VERSION 5.8 ;
BUSBITCHARS "[]" ;
DIVIDERCHAR "/" ;
UNITS
    DATABASE MICRONS 1000 ;
END UNITS

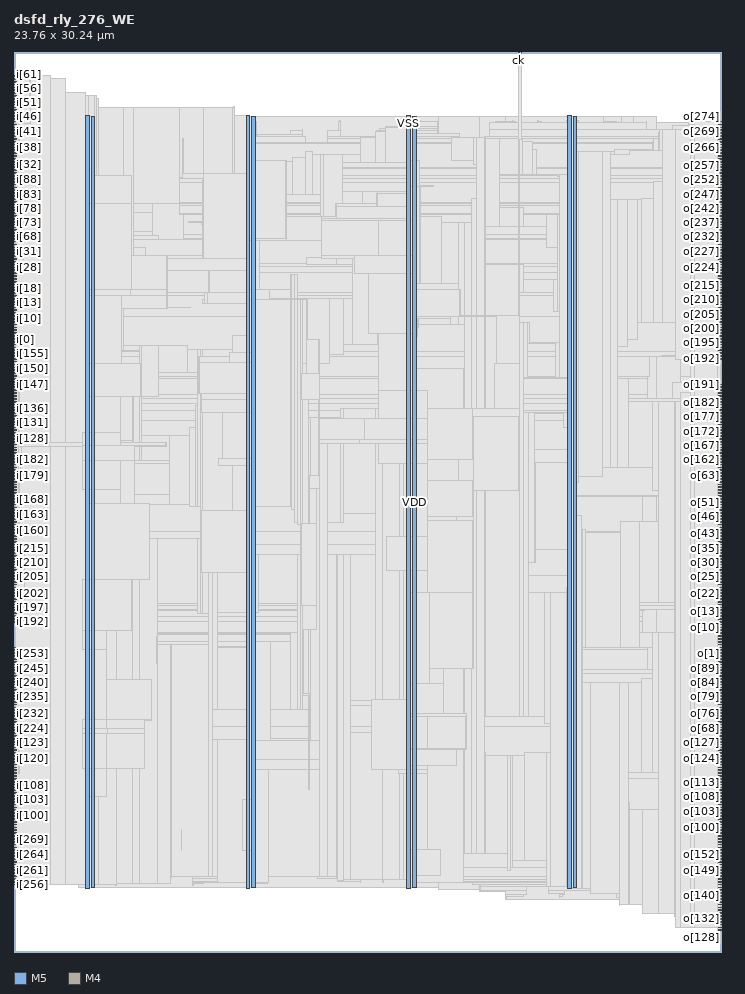
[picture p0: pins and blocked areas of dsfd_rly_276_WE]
MACRO dsfd_rly_276_WE
  FOREIGN dsfd_rly_276_WE 0 0 ;
  CLASS BLOCK ;
  SIZE 23.76 BY 30.24 ;
  PIN ck
    DIRECTION INPUT ;
    USE SIGNAL ;
    PORT
      LAYER M5 ;
        RECT  16.944 30.156 16.968 30.24 ;
    END
  END ck
  PIN i[0]
    DIRECTION INPUT ;
    USE SIGNAL ;
    PORT
      LAYER M4 ;
        RECT  0 20.304 0.084 20.328 ;
    END
  END i[0]
  PIN i[100]
    DIRECTION INPUT ;
    USE SIGNAL ;
    PORT
      LAYER M4 ;
        RECT  0 4.56 0.084 4.584 ;
    END
  END i[100]
  PIN i[101]
    DIRECTION INPUT ;
    USE SIGNAL ;
    PORT
      LAYER M4 ;
        RECT  0 4.656 0.084 4.68 ;
    END
  END i[101]
  PIN i[102]
    DIRECTION INPUT ;
    USE SIGNAL ;
    PORT
      LAYER M4 ;
        RECT  0 4.752 0.084 4.776 ;
    END
  END i[102]
  PIN i[103]
    DIRECTION INPUT ;
    USE SIGNAL ;
    PORT
      LAYER M4 ;
        RECT  0 4.848 0.084 4.872 ;
    END
  END i[103]
  PIN i[104]
    DIRECTION INPUT ;
    USE SIGNAL ;
    PORT
      LAYER M4 ;
        RECT  0 4.944 0.084 4.968 ;
    END
  END i[104]
  PIN i[105]
    DIRECTION INPUT ;
    USE SIGNAL ;
    PORT
      LAYER M4 ;
        RECT  0 5.04 0.084 5.064 ;
    END
  END i[105]
  PIN i[106]
    DIRECTION INPUT ;
    USE SIGNAL ;
    PORT
      LAYER M4 ;
        RECT  0 5.136 0.084 5.16 ;
    END
  END i[106]
  PIN i[107]
    DIRECTION INPUT ;
    USE SIGNAL ;
    PORT
      LAYER M4 ;
        RECT  0 5.232 0.084 5.256 ;
    END
  END i[107]
  PIN i[108]
    DIRECTION INPUT ;
    USE SIGNAL ;
    PORT
      LAYER M4 ;
        RECT  0 5.328 0.084 5.352 ;
    END
  END i[108]
  PIN i[109]
    DIRECTION INPUT ;
    USE SIGNAL ;
    PORT
      LAYER M4 ;
        RECT  0 5.424 0.084 5.448 ;
    END
  END i[109]
  PIN i[10]
    DIRECTION INPUT ;
    USE SIGNAL ;
    PORT
      LAYER M4 ;
        RECT  0 21.264 0.084 21.288 ;
    END
  END i[10]
  PIN i[110]
    DIRECTION INPUT ;
    USE SIGNAL ;
    PORT
      LAYER M4 ;
        RECT  0 5.52 0.084 5.544 ;
    END
  END i[110]
  PIN i[111]
    DIRECTION INPUT ;
    USE SIGNAL ;
    PORT
      LAYER M4 ;
        RECT  0 5.616 0.084 5.64 ;
    END
  END i[111]
  PIN i[112]
    DIRECTION INPUT ;
    USE SIGNAL ;
    PORT
      LAYER M4 ;
        RECT  0 5.712 0.084 5.736 ;
    END
  END i[112]
  PIN i[113]
    DIRECTION INPUT ;
    USE SIGNAL ;
    PORT
      LAYER M4 ;
        RECT  0 5.808 0.084 5.832 ;
    END
  END i[113]
  PIN i[114]
    DIRECTION INPUT ;
    USE SIGNAL ;
    PORT
      LAYER M4 ;
        RECT  0 5.904 0.084 5.928 ;
    END
  END i[114]
  PIN i[115]
    DIRECTION INPUT ;
    USE SIGNAL ;
    PORT
      LAYER M4 ;
        RECT  0 6 0.084 6.024 ;
    END
  END i[115]
  PIN i[116]
    DIRECTION INPUT ;
    USE SIGNAL ;
    PORT
      LAYER M4 ;
        RECT  0 6.096 0.084 6.12 ;
    END
  END i[116]
  PIN i[117]
    DIRECTION INPUT ;
    USE SIGNAL ;
    PORT
      LAYER M4 ;
        RECT  0 6.192 0.084 6.216 ;
    END
  END i[117]
  PIN i[118]
    DIRECTION INPUT ;
    USE SIGNAL ;
    PORT
      LAYER M4 ;
        RECT  0 6.288 0.084 6.312 ;
    END
  END i[118]
  PIN i[119]
    DIRECTION INPUT ;
    USE SIGNAL ;
    PORT
      LAYER M4 ;
        RECT  0 6.384 0.084 6.408 ;
    END
  END i[119]
  PIN i[11]
    DIRECTION INPUT ;
    USE SIGNAL ;
    PORT
      LAYER M4 ;
        RECT  0 21.36 0.084 21.384 ;
    END
  END i[11]
  PIN i[120]
    DIRECTION INPUT ;
    USE SIGNAL ;
    PORT
      LAYER M4 ;
        RECT  0 6.48 0.084 6.504 ;
    END
  END i[120]
  PIN i[121]
    DIRECTION INPUT ;
    USE SIGNAL ;
    PORT
      LAYER M4 ;
        RECT  0 6.576 0.084 6.6 ;
    END
  END i[121]
  PIN i[122]
    DIRECTION INPUT ;
    USE SIGNAL ;
    PORT
      LAYER M4 ;
        RECT  0 6.672 0.084 6.696 ;
    END
  END i[122]
  PIN i[123]
    DIRECTION INPUT ;
    USE SIGNAL ;
    PORT
      LAYER M4 ;
        RECT  0 6.768 0.084 6.792 ;
    END
  END i[123]
  PIN i[124]
    DIRECTION INPUT ;
    USE SIGNAL ;
    PORT
      LAYER M4 ;
        RECT  0 6.864 0.084 6.888 ;
    END
  END i[124]
  PIN i[125]
    DIRECTION INPUT ;
    USE SIGNAL ;
    PORT
      LAYER M4 ;
        RECT  0 6.96 0.084 6.984 ;
    END
  END i[125]
  PIN i[126]
    DIRECTION INPUT ;
    USE SIGNAL ;
    PORT
      LAYER M4 ;
        RECT  0 7.056 0.084 7.08 ;
    END
  END i[126]
  PIN i[127]
    DIRECTION INPUT ;
    USE SIGNAL ;
    PORT
      LAYER M4 ;
        RECT  0 7.152 0.084 7.176 ;
    END
  END i[127]
  PIN i[128]
    DIRECTION INPUT ;
    USE SIGNAL ;
    PORT
      LAYER M4 ;
        RECT  0 17.232 0.084 17.256 ;
    END
  END i[128]
  PIN i[129]
    DIRECTION INPUT ;
    USE SIGNAL ;
    PORT
      LAYER M4 ;
        RECT  0 17.328 0.084 17.352 ;
    END
  END i[129]
  PIN i[12]
    DIRECTION INPUT ;
    USE SIGNAL ;
    PORT
      LAYER M4 ;
        RECT  0 21.456 0.084 21.48 ;
    END
  END i[12]
  PIN i[130]
    DIRECTION INPUT ;
    USE SIGNAL ;
    PORT
      LAYER M4 ;
        RECT  0 17.424 0.084 17.448 ;
    END
  END i[130]
  PIN i[131]
    DIRECTION INPUT ;
    USE SIGNAL ;
    PORT
      LAYER M4 ;
        RECT  0 17.52 0.084 17.544 ;
    END
  END i[131]
  PIN i[132]
    DIRECTION INPUT ;
    USE SIGNAL ;
    PORT
      LAYER M4 ;
        RECT  0 17.616 0.084 17.64 ;
    END
  END i[132]
  PIN i[133]
    DIRECTION INPUT ;
    USE SIGNAL ;
    PORT
      LAYER M4 ;
        RECT  0 17.712 0.084 17.736 ;
    END
  END i[133]
  PIN i[134]
    DIRECTION INPUT ;
    USE SIGNAL ;
    PORT
      LAYER M4 ;
        RECT  0 17.808 0.084 17.832 ;
    END
  END i[134]
  PIN i[135]
    DIRECTION INPUT ;
    USE SIGNAL ;
    PORT
      LAYER M4 ;
        RECT  0 17.904 0.084 17.928 ;
    END
  END i[135]
  PIN i[136]
    DIRECTION INPUT ;
    USE SIGNAL ;
    PORT
      LAYER M4 ;
        RECT  0 18 0.084 18.024 ;
    END
  END i[136]
  PIN i[137]
    DIRECTION INPUT ;
    USE SIGNAL ;
    PORT
      LAYER M4 ;
        RECT  0 18.096 0.084 18.12 ;
    END
  END i[137]
  PIN i[138]
    DIRECTION INPUT ;
    USE SIGNAL ;
    PORT
      LAYER M4 ;
        RECT  0 18.192 0.084 18.216 ;
    END
  END i[138]
  PIN i[139]
    DIRECTION INPUT ;
    USE SIGNAL ;
    PORT
      LAYER M4 ;
        RECT  0 18.288 0.084 18.312 ;
    END
  END i[139]
  PIN i[13]
    DIRECTION INPUT ;
    USE SIGNAL ;
    PORT
      LAYER M4 ;
        RECT  0 21.552 0.084 21.576 ;
    END
  END i[13]
  PIN i[140]
    DIRECTION INPUT ;
    USE SIGNAL ;
    PORT
      LAYER M4 ;
        RECT  0 18.384 0.084 18.408 ;
    END
  END i[140]
  PIN i[141]
    DIRECTION INPUT ;
    USE SIGNAL ;
    PORT
      LAYER M4 ;
        RECT  0 18.48 0.084 18.504 ;
    END
  END i[141]
  PIN i[142]
    DIRECTION INPUT ;
    USE SIGNAL ;
    PORT
      LAYER M4 ;
        RECT  0 18.576 0.084 18.6 ;
    END
  END i[142]
  PIN i[143]
    DIRECTION INPUT ;
    USE SIGNAL ;
    PORT
      LAYER M4 ;
        RECT  0 18.672 0.084 18.696 ;
    END
  END i[143]
  PIN i[144]
    DIRECTION INPUT ;
    USE SIGNAL ;
    PORT
      LAYER M4 ;
        RECT  0 18.768 0.084 18.792 ;
    END
  END i[144]
  PIN i[145]
    DIRECTION INPUT ;
    USE SIGNAL ;
    PORT
      LAYER M4 ;
        RECT  0 18.864 0.084 18.888 ;
    END
  END i[145]
  PIN i[146]
    DIRECTION INPUT ;
    USE SIGNAL ;
    PORT
      LAYER M4 ;
        RECT  0 18.96 0.084 18.984 ;
    END
  END i[146]
  PIN i[147]
    DIRECTION INPUT ;
    USE SIGNAL ;
    PORT
      LAYER M4 ;
        RECT  0 19.056 0.084 19.08 ;
    END
  END i[147]
  PIN i[148]
    DIRECTION INPUT ;
    USE SIGNAL ;
    PORT
      LAYER M4 ;
        RECT  0 19.152 0.084 19.176 ;
    END
  END i[148]
  PIN i[149]
    DIRECTION INPUT ;
    USE SIGNAL ;
    PORT
      LAYER M4 ;
        RECT  0 19.248 0.084 19.272 ;
    END
  END i[149]
  PIN i[14]
    DIRECTION INPUT ;
    USE SIGNAL ;
    PORT
      LAYER M4 ;
        RECT  0 21.648 0.084 21.672 ;
    END
  END i[14]
  PIN i[150]
    DIRECTION INPUT ;
    USE SIGNAL ;
    PORT
      LAYER M4 ;
        RECT  0 19.344 0.084 19.368 ;
    END
  END i[150]
  PIN i[151]
    DIRECTION INPUT ;
    USE SIGNAL ;
    PORT
      LAYER M4 ;
        RECT  0 19.44 0.084 19.464 ;
    END
  END i[151]
  PIN i[152]
    DIRECTION INPUT ;
    USE SIGNAL ;
    PORT
      LAYER M4 ;
        RECT  0 19.536 0.084 19.56 ;
    END
  END i[152]
  PIN i[153]
    DIRECTION INPUT ;
    USE SIGNAL ;
    PORT
      LAYER M4 ;
        RECT  0 19.632 0.084 19.656 ;
    END
  END i[153]
  PIN i[154]
    DIRECTION INPUT ;
    USE SIGNAL ;
    PORT
      LAYER M4 ;
        RECT  0 19.728 0.084 19.752 ;
    END
  END i[154]
  PIN i[155]
    DIRECTION INPUT ;
    USE SIGNAL ;
    PORT
      LAYER M4 ;
        RECT  0 19.824 0.084 19.848 ;
    END
  END i[155]
  PIN i[156]
    DIRECTION INPUT ;
    USE SIGNAL ;
    PORT
      LAYER M4 ;
        RECT  0 19.92 0.084 19.944 ;
    END
  END i[156]
  PIN i[157]
    DIRECTION INPUT ;
    USE SIGNAL ;
    PORT
      LAYER M4 ;
        RECT  0 20.016 0.084 20.04 ;
    END
  END i[157]
  PIN i[158]
    DIRECTION INPUT ;
    USE SIGNAL ;
    PORT
      LAYER M4 ;
        RECT  0 20.112 0.084 20.136 ;
    END
  END i[158]
  PIN i[159]
    DIRECTION INPUT ;
    USE SIGNAL ;
    PORT
      LAYER M4 ;
        RECT  0 20.208 0.084 20.232 ;
    END
  END i[159]
  PIN i[15]
    DIRECTION INPUT ;
    USE SIGNAL ;
    PORT
      LAYER M4 ;
        RECT  0 21.744 0.084 21.768 ;
    END
  END i[15]
  PIN i[160]
    DIRECTION INPUT ;
    USE SIGNAL ;
    PORT
      LAYER M4 ;
        RECT  0 14.16 0.084 14.184 ;
    END
  END i[160]
  PIN i[161]
    DIRECTION INPUT ;
    USE SIGNAL ;
    PORT
      LAYER M4 ;
        RECT  0 14.256 0.084 14.28 ;
    END
  END i[161]
  PIN i[162]
    DIRECTION INPUT ;
    USE SIGNAL ;
    PORT
      LAYER M4 ;
        RECT  0 14.352 0.084 14.376 ;
    END
  END i[162]
  PIN i[163]
    DIRECTION INPUT ;
    USE SIGNAL ;
    PORT
      LAYER M4 ;
        RECT  0 14.448 0.084 14.472 ;
    END
  END i[163]
  PIN i[164]
    DIRECTION INPUT ;
    USE SIGNAL ;
    PORT
      LAYER M4 ;
        RECT  0 14.544 0.084 14.568 ;
    END
  END i[164]
  PIN i[165]
    DIRECTION INPUT ;
    USE SIGNAL ;
    PORT
      LAYER M4 ;
        RECT  0 14.64 0.084 14.664 ;
    END
  END i[165]
  PIN i[166]
    DIRECTION INPUT ;
    USE SIGNAL ;
    PORT
      LAYER M4 ;
        RECT  0 14.736 0.084 14.76 ;
    END
  END i[166]
  PIN i[167]
    DIRECTION INPUT ;
    USE SIGNAL ;
    PORT
      LAYER M4 ;
        RECT  0 14.832 0.084 14.856 ;
    END
  END i[167]
  PIN i[168]
    DIRECTION INPUT ;
    USE SIGNAL ;
    PORT
      LAYER M4 ;
        RECT  0 14.928 0.084 14.952 ;
    END
  END i[168]
  PIN i[169]
    DIRECTION INPUT ;
    USE SIGNAL ;
    PORT
      LAYER M4 ;
        RECT  0 15.024 0.084 15.048 ;
    END
  END i[169]
  PIN i[16]
    DIRECTION INPUT ;
    USE SIGNAL ;
    PORT
      LAYER M4 ;
        RECT  0 21.84 0.084 21.864 ;
    END
  END i[16]
  PIN i[170]
    DIRECTION INPUT ;
    USE SIGNAL ;
    PORT
      LAYER M4 ;
        RECT  0 15.12 0.084 15.144 ;
    END
  END i[170]
  PIN i[171]
    DIRECTION INPUT ;
    USE SIGNAL ;
    PORT
      LAYER M4 ;
        RECT  0 15.216 0.084 15.24 ;
    END
  END i[171]
  PIN i[172]
    DIRECTION INPUT ;
    USE SIGNAL ;
    PORT
      LAYER M4 ;
        RECT  0 15.312 0.084 15.336 ;
    END
  END i[172]
  PIN i[173]
    DIRECTION INPUT ;
    USE SIGNAL ;
    PORT
      LAYER M4 ;
        RECT  0 15.408 0.084 15.432 ;
    END
  END i[173]
  PIN i[174]
    DIRECTION INPUT ;
    USE SIGNAL ;
    PORT
      LAYER M4 ;
        RECT  0 15.504 0.084 15.528 ;
    END
  END i[174]
  PIN i[175]
    DIRECTION INPUT ;
    USE SIGNAL ;
    PORT
      LAYER M4 ;
        RECT  0 15.6 0.084 15.624 ;
    END
  END i[175]
  PIN i[176]
    DIRECTION INPUT ;
    USE SIGNAL ;
    PORT
      LAYER M4 ;
        RECT  0 15.696 0.084 15.72 ;
    END
  END i[176]
  PIN i[177]
    DIRECTION INPUT ;
    USE SIGNAL ;
    PORT
      LAYER M4 ;
        RECT  0 15.792 0.084 15.816 ;
    END
  END i[177]
  PIN i[178]
    DIRECTION INPUT ;
    USE SIGNAL ;
    PORT
      LAYER M4 ;
        RECT  0 15.888 0.084 15.912 ;
    END
  END i[178]
  PIN i[179]
    DIRECTION INPUT ;
    USE SIGNAL ;
    PORT
      LAYER M4 ;
        RECT  0 15.984 0.084 16.008 ;
    END
  END i[179]
  PIN i[17]
    DIRECTION INPUT ;
    USE SIGNAL ;
    PORT
      LAYER M4 ;
        RECT  0 21.936 0.084 21.96 ;
    END
  END i[17]
  PIN i[180]
    DIRECTION INPUT ;
    USE SIGNAL ;
    PORT
      LAYER M4 ;
        RECT  0 16.08 0.084 16.104 ;
    END
  END i[180]
  PIN i[181]
    DIRECTION INPUT ;
    USE SIGNAL ;
    PORT
      LAYER M4 ;
        RECT  0 16.176 0.084 16.2 ;
    END
  END i[181]
  PIN i[182]
    DIRECTION INPUT ;
    USE SIGNAL ;
    PORT
      LAYER M4 ;
        RECT  0 16.272 0.084 16.296 ;
    END
  END i[182]
  PIN i[183]
    DIRECTION INPUT ;
    USE SIGNAL ;
    PORT
      LAYER M4 ;
        RECT  0 16.368 0.084 16.392 ;
    END
  END i[183]
  PIN i[184]
    DIRECTION INPUT ;
    USE SIGNAL ;
    PORT
      LAYER M4 ;
        RECT  0 16.464 0.084 16.488 ;
    END
  END i[184]
  PIN i[185]
    DIRECTION INPUT ;
    USE SIGNAL ;
    PORT
      LAYER M4 ;
        RECT  0 16.56 0.084 16.584 ;
    END
  END i[185]
  PIN i[186]
    DIRECTION INPUT ;
    USE SIGNAL ;
    PORT
      LAYER M4 ;
        RECT  0 16.656 0.084 16.68 ;
    END
  END i[186]
  PIN i[187]
    DIRECTION INPUT ;
    USE SIGNAL ;
    PORT
      LAYER M4 ;
        RECT  0 16.752 0.084 16.776 ;
    END
  END i[187]
  PIN i[188]
    DIRECTION INPUT ;
    USE SIGNAL ;
    PORT
      LAYER M4 ;
        RECT  0 16.848 0.084 16.872 ;
    END
  END i[188]
  PIN i[189]
    DIRECTION INPUT ;
    USE SIGNAL ;
    PORT
      LAYER M4 ;
        RECT  0 16.944 0.084 16.968 ;
    END
  END i[189]
  PIN i[18]
    DIRECTION INPUT ;
    USE SIGNAL ;
    PORT
      LAYER M4 ;
        RECT  0 22.032 0.084 22.056 ;
    END
  END i[18]
  PIN i[190]
    DIRECTION INPUT ;
    USE SIGNAL ;
    PORT
      LAYER M4 ;
        RECT  0 17.04 0.084 17.064 ;
    END
  END i[190]
  PIN i[191]
    DIRECTION INPUT ;
    USE SIGNAL ;
    PORT
      LAYER M4 ;
        RECT  0 17.136 0.084 17.16 ;
    END
  END i[191]
  PIN i[192]
    DIRECTION INPUT ;
    USE SIGNAL ;
    PORT
      LAYER M4 ;
        RECT  0 11.088 0.084 11.112 ;
    END
  END i[192]
  PIN i[193]
    DIRECTION INPUT ;
    USE SIGNAL ;
    PORT
      LAYER M4 ;
        RECT  0 11.184 0.084 11.208 ;
    END
  END i[193]
  PIN i[194]
    DIRECTION INPUT ;
    USE SIGNAL ;
    PORT
      LAYER M4 ;
        RECT  0 11.28 0.084 11.304 ;
    END
  END i[194]
  PIN i[195]
    DIRECTION INPUT ;
    USE SIGNAL ;
    PORT
      LAYER M4 ;
        RECT  0 11.376 0.084 11.4 ;
    END
  END i[195]
  PIN i[196]
    DIRECTION INPUT ;
    USE SIGNAL ;
    PORT
      LAYER M4 ;
        RECT  0 11.472 0.084 11.496 ;
    END
  END i[196]
  PIN i[197]
    DIRECTION INPUT ;
    USE SIGNAL ;
    PORT
      LAYER M4 ;
        RECT  0 11.568 0.084 11.592 ;
    END
  END i[197]
  PIN i[198]
    DIRECTION INPUT ;
    USE SIGNAL ;
    PORT
      LAYER M4 ;
        RECT  0 11.664 0.084 11.688 ;
    END
  END i[198]
  PIN i[199]
    DIRECTION INPUT ;
    USE SIGNAL ;
    PORT
      LAYER M4 ;
        RECT  0 11.76 0.084 11.784 ;
    END
  END i[199]
  PIN i[19]
    DIRECTION INPUT ;
    USE SIGNAL ;
    PORT
      LAYER M4 ;
        RECT  0 22.128 0.084 22.152 ;
    END
  END i[19]
  PIN i[1]
    DIRECTION INPUT ;
    USE SIGNAL ;
    PORT
      LAYER M4 ;
        RECT  0 20.4 0.084 20.424 ;
    END
  END i[1]
  PIN i[200]
    DIRECTION INPUT ;
    USE SIGNAL ;
    PORT
      LAYER M4 ;
        RECT  0 11.856 0.084 11.88 ;
    END
  END i[200]
  PIN i[201]
    DIRECTION INPUT ;
    USE SIGNAL ;
    PORT
      LAYER M4 ;
        RECT  0 11.952 0.084 11.976 ;
    END
  END i[201]
  PIN i[202]
    DIRECTION INPUT ;
    USE SIGNAL ;
    PORT
      LAYER M4 ;
        RECT  0 12.048 0.084 12.072 ;
    END
  END i[202]
  PIN i[203]
    DIRECTION INPUT ;
    USE SIGNAL ;
    PORT
      LAYER M4 ;
        RECT  0 12.144 0.084 12.168 ;
    END
  END i[203]
  PIN i[204]
    DIRECTION INPUT ;
    USE SIGNAL ;
    PORT
      LAYER M4 ;
        RECT  0 12.24 0.084 12.264 ;
    END
  END i[204]
  PIN i[205]
    DIRECTION INPUT ;
    USE SIGNAL ;
    PORT
      LAYER M4 ;
        RECT  0 12.336 0.084 12.36 ;
    END
  END i[205]
  PIN i[206]
    DIRECTION INPUT ;
    USE SIGNAL ;
    PORT
      LAYER M4 ;
        RECT  0 12.432 0.084 12.456 ;
    END
  END i[206]
  PIN i[207]
    DIRECTION INPUT ;
    USE SIGNAL ;
    PORT
      LAYER M4 ;
        RECT  0 12.528 0.084 12.552 ;
    END
  END i[207]
  PIN i[208]
    DIRECTION INPUT ;
    USE SIGNAL ;
    PORT
      LAYER M4 ;
        RECT  0 12.624 0.084 12.648 ;
    END
  END i[208]
  PIN i[209]
    DIRECTION INPUT ;
    USE SIGNAL ;
    PORT
      LAYER M4 ;
        RECT  0 12.72 0.084 12.744 ;
    END
  END i[209]
  PIN i[20]
    DIRECTION INPUT ;
    USE SIGNAL ;
    PORT
      LAYER M4 ;
        RECT  0 22.224 0.084 22.248 ;
    END
  END i[20]
  PIN i[210]
    DIRECTION INPUT ;
    USE SIGNAL ;
    PORT
      LAYER M4 ;
        RECT  0 12.816 0.084 12.84 ;
    END
  END i[210]
  PIN i[211]
    DIRECTION INPUT ;
    USE SIGNAL ;
    PORT
      LAYER M4 ;
        RECT  0 12.912 0.084 12.936 ;
    END
  END i[211]
  PIN i[212]
    DIRECTION INPUT ;
    USE SIGNAL ;
    PORT
      LAYER M4 ;
        RECT  0 13.008 0.084 13.032 ;
    END
  END i[212]
  PIN i[213]
    DIRECTION INPUT ;
    USE SIGNAL ;
    PORT
      LAYER M4 ;
        RECT  0 13.104 0.084 13.128 ;
    END
  END i[213]
  PIN i[214]
    DIRECTION INPUT ;
    USE SIGNAL ;
    PORT
      LAYER M4 ;
        RECT  0 13.2 0.084 13.224 ;
    END
  END i[214]
  PIN i[215]
    DIRECTION INPUT ;
    USE SIGNAL ;
    PORT
      LAYER M4 ;
        RECT  0 13.296 0.084 13.32 ;
    END
  END i[215]
  PIN i[216]
    DIRECTION INPUT ;
    USE SIGNAL ;
    PORT
      LAYER M4 ;
        RECT  0 13.392 0.084 13.416 ;
    END
  END i[216]
  PIN i[217]
    DIRECTION INPUT ;
    USE SIGNAL ;
    PORT
      LAYER M4 ;
        RECT  0 13.488 0.084 13.512 ;
    END
  END i[217]
  PIN i[218]
    DIRECTION INPUT ;
    USE SIGNAL ;
    PORT
      LAYER M4 ;
        RECT  0 13.584 0.084 13.608 ;
    END
  END i[218]
  PIN i[219]
    DIRECTION INPUT ;
    USE SIGNAL ;
    PORT
      LAYER M4 ;
        RECT  0 13.68 0.084 13.704 ;
    END
  END i[219]
  PIN i[21]
    DIRECTION INPUT ;
    USE SIGNAL ;
    PORT
      LAYER M4 ;
        RECT  0 22.32 0.084 22.344 ;
    END
  END i[21]
  PIN i[220]
    DIRECTION INPUT ;
    USE SIGNAL ;
    PORT
      LAYER M4 ;
        RECT  0 13.776 0.084 13.8 ;
    END
  END i[220]
  PIN i[221]
    DIRECTION INPUT ;
    USE SIGNAL ;
    PORT
      LAYER M4 ;
        RECT  0 13.872 0.084 13.896 ;
    END
  END i[221]
  PIN i[222]
    DIRECTION INPUT ;
    USE SIGNAL ;
    PORT
      LAYER M4 ;
        RECT  0 13.968 0.084 13.992 ;
    END
  END i[222]
  PIN i[223]
    DIRECTION INPUT ;
    USE SIGNAL ;
    PORT
      LAYER M4 ;
        RECT  0 14.064 0.084 14.088 ;
    END
  END i[223]
  PIN i[224]
    DIRECTION INPUT ;
    USE SIGNAL ;
    PORT
      LAYER M4 ;
        RECT  0 7.248 0.084 7.272 ;
    END
  END i[224]
  PIN i[225]
    DIRECTION INPUT ;
    USE SIGNAL ;
    PORT
      LAYER M4 ;
        RECT  0 7.344 0.084 7.368 ;
    END
  END i[225]
  PIN i[226]
    DIRECTION INPUT ;
    USE SIGNAL ;
    PORT
      LAYER M4 ;
        RECT  0 7.44 0.084 7.464 ;
    END
  END i[226]
  PIN i[227]
    DIRECTION INPUT ;
    USE SIGNAL ;
    PORT
      LAYER M4 ;
        RECT  0 7.536 0.084 7.56 ;
    END
  END i[227]
  PIN i[228]
    DIRECTION INPUT ;
    USE SIGNAL ;
    PORT
      LAYER M4 ;
        RECT  0 7.632 0.084 7.656 ;
    END
  END i[228]
  PIN i[229]
    DIRECTION INPUT ;
    USE SIGNAL ;
    PORT
      LAYER M4 ;
        RECT  0 7.728 0.084 7.752 ;
    END
  END i[229]
  PIN i[22]
    DIRECTION INPUT ;
    USE SIGNAL ;
    PORT
      LAYER M4 ;
        RECT  0 22.416 0.084 22.44 ;
    END
  END i[22]
  PIN i[230]
    DIRECTION INPUT ;
    USE SIGNAL ;
    PORT
      LAYER M4 ;
        RECT  0 7.824 0.084 7.848 ;
    END
  END i[230]
  PIN i[231]
    DIRECTION INPUT ;
    USE SIGNAL ;
    PORT
      LAYER M4 ;
        RECT  0 7.92 0.084 7.944 ;
    END
  END i[231]
  PIN i[232]
    DIRECTION INPUT ;
    USE SIGNAL ;
    PORT
      LAYER M4 ;
        RECT  0 8.016 0.084 8.04 ;
    END
  END i[232]
  PIN i[233]
    DIRECTION INPUT ;
    USE SIGNAL ;
    PORT
      LAYER M4 ;
        RECT  0 8.112 0.084 8.136 ;
    END
  END i[233]
  PIN i[234]
    DIRECTION INPUT ;
    USE SIGNAL ;
    PORT
      LAYER M4 ;
        RECT  0 8.208 0.084 8.232 ;
    END
  END i[234]
  PIN i[235]
    DIRECTION INPUT ;
    USE SIGNAL ;
    PORT
      LAYER M4 ;
        RECT  0 8.304 0.084 8.328 ;
    END
  END i[235]
  PIN i[236]
    DIRECTION INPUT ;
    USE SIGNAL ;
    PORT
      LAYER M4 ;
        RECT  0 8.4 0.084 8.424 ;
    END
  END i[236]
  PIN i[237]
    DIRECTION INPUT ;
    USE SIGNAL ;
    PORT
      LAYER M4 ;
        RECT  0 8.496 0.084 8.52 ;
    END
  END i[237]
  PIN i[238]
    DIRECTION INPUT ;
    USE SIGNAL ;
    PORT
      LAYER M4 ;
        RECT  0 8.592 0.084 8.616 ;
    END
  END i[238]
  PIN i[239]
    DIRECTION INPUT ;
    USE SIGNAL ;
    PORT
      LAYER M4 ;
        RECT  0 8.688 0.084 8.712 ;
    END
  END i[239]
  PIN i[23]
    DIRECTION INPUT ;
    USE SIGNAL ;
    PORT
      LAYER M4 ;
        RECT  0 22.512 0.084 22.536 ;
    END
  END i[23]
  PIN i[240]
    DIRECTION INPUT ;
    USE SIGNAL ;
    PORT
      LAYER M4 ;
        RECT  0 8.784 0.084 8.808 ;
    END
  END i[240]
  PIN i[241]
    DIRECTION INPUT ;
    USE SIGNAL ;
    PORT
      LAYER M4 ;
        RECT  0 8.88 0.084 8.904 ;
    END
  END i[241]
  PIN i[242]
    DIRECTION INPUT ;
    USE SIGNAL ;
    PORT
      LAYER M4 ;
        RECT  0 8.976 0.084 9 ;
    END
  END i[242]
  PIN i[243]
    DIRECTION INPUT ;
    USE SIGNAL ;
    PORT
      LAYER M4 ;
        RECT  0 9.072 0.084 9.096 ;
    END
  END i[243]
  PIN i[244]
    DIRECTION INPUT ;
    USE SIGNAL ;
    PORT
      LAYER M4 ;
        RECT  0 9.168 0.084 9.192 ;
    END
  END i[244]
  PIN i[245]
    DIRECTION INPUT ;
    USE SIGNAL ;
    PORT
      LAYER M4 ;
        RECT  0 9.264 0.084 9.288 ;
    END
  END i[245]
  PIN i[246]
    DIRECTION INPUT ;
    USE SIGNAL ;
    PORT
      LAYER M4 ;
        RECT  0 9.36 0.084 9.384 ;
    END
  END i[246]
  PIN i[247]
    DIRECTION INPUT ;
    USE SIGNAL ;
    PORT
      LAYER M4 ;
        RECT  0 9.456 0.084 9.48 ;
    END
  END i[247]
  PIN i[248]
    DIRECTION INPUT ;
    USE SIGNAL ;
    PORT
      LAYER M4 ;
        RECT  0 9.552 0.084 9.576 ;
    END
  END i[248]
  PIN i[249]
    DIRECTION INPUT ;
    USE SIGNAL ;
    PORT
      LAYER M4 ;
        RECT  0 9.648 0.084 9.672 ;
    END
  END i[249]
  PIN i[24]
    DIRECTION INPUT ;
    USE SIGNAL ;
    PORT
      LAYER M4 ;
        RECT  0 22.608 0.084 22.632 ;
    END
  END i[24]
  PIN i[250]
    DIRECTION INPUT ;
    USE SIGNAL ;
    PORT
      LAYER M4 ;
        RECT  0 9.744 0.084 9.768 ;
    END
  END i[250]
  PIN i[251]
    DIRECTION INPUT ;
    USE SIGNAL ;
    PORT
      LAYER M4 ;
        RECT  0 9.84 0.084 9.864 ;
    END
  END i[251]
  PIN i[252]
    DIRECTION INPUT ;
    USE SIGNAL ;
    PORT
      LAYER M4 ;
        RECT  0 9.936 0.084 9.96 ;
    END
  END i[252]
  PIN i[253]
    DIRECTION INPUT ;
    USE SIGNAL ;
    PORT
      LAYER M4 ;
        RECT  0 10.032 0.084 10.056 ;
    END
  END i[253]
  PIN i[254]
    DIRECTION INPUT ;
    USE SIGNAL ;
    PORT
      LAYER M4 ;
        RECT  0 10.128 0.084 10.152 ;
    END
  END i[254]
  PIN i[255]
    DIRECTION INPUT ;
    USE SIGNAL ;
    PORT
      LAYER M4 ;
        RECT  0 10.224 0.084 10.248 ;
    END
  END i[255]
  PIN i[256]
    DIRECTION INPUT ;
    USE SIGNAL ;
    PORT
      LAYER M4 ;
        RECT  0 2.256 0.084 2.28 ;
    END
  END i[256]
  PIN i[257]
    DIRECTION INPUT ;
    USE SIGNAL ;
    PORT
      LAYER M4 ;
        RECT  0 2.352 0.084 2.376 ;
    END
  END i[257]
  PIN i[258]
    DIRECTION INPUT ;
    USE SIGNAL ;
    PORT
      LAYER M4 ;
        RECT  0 2.448 0.084 2.472 ;
    END
  END i[258]
  PIN i[259]
    DIRECTION INPUT ;
    USE SIGNAL ;
    PORT
      LAYER M4 ;
        RECT  0 2.544 0.084 2.568 ;
    END
  END i[259]
  PIN i[25]
    DIRECTION INPUT ;
    USE SIGNAL ;
    PORT
      LAYER M4 ;
        RECT  0 22.704 0.084 22.728 ;
    END
  END i[25]
  PIN i[260]
    DIRECTION INPUT ;
    USE SIGNAL ;
    PORT
      LAYER M4 ;
        RECT  0 2.64 0.084 2.664 ;
    END
  END i[260]
  PIN i[261]
    DIRECTION INPUT ;
    USE SIGNAL ;
    PORT
      LAYER M4 ;
        RECT  0 2.736 0.084 2.76 ;
    END
  END i[261]
  PIN i[262]
    DIRECTION INPUT ;
    USE SIGNAL ;
    PORT
      LAYER M4 ;
        RECT  0 2.832 0.084 2.856 ;
    END
  END i[262]
  PIN i[263]
    DIRECTION INPUT ;
    USE SIGNAL ;
    PORT
      LAYER M4 ;
        RECT  0 2.928 0.084 2.952 ;
    END
  END i[263]
  PIN i[264]
    DIRECTION INPUT ;
    USE SIGNAL ;
    PORT
      LAYER M4 ;
        RECT  0 3.024 0.084 3.048 ;
    END
  END i[264]
  PIN i[265]
    DIRECTION INPUT ;
    USE SIGNAL ;
    PORT
      LAYER M4 ;
        RECT  0 3.12 0.084 3.144 ;
    END
  END i[265]
  PIN i[266]
    DIRECTION INPUT ;
    USE SIGNAL ;
    PORT
      LAYER M4 ;
        RECT  0 3.216 0.084 3.24 ;
    END
  END i[266]
  PIN i[267]
    DIRECTION INPUT ;
    USE SIGNAL ;
    PORT
      LAYER M4 ;
        RECT  0 3.312 0.084 3.336 ;
    END
  END i[267]
  PIN i[268]
    DIRECTION INPUT ;
    USE SIGNAL ;
    PORT
      LAYER M4 ;
        RECT  0 3.408 0.084 3.432 ;
    END
  END i[268]
  PIN i[269]
    DIRECTION INPUT ;
    USE SIGNAL ;
    PORT
      LAYER M4 ;
        RECT  0 3.504 0.084 3.528 ;
    END
  END i[269]
  PIN i[26]
    DIRECTION INPUT ;
    USE SIGNAL ;
    PORT
      LAYER M4 ;
        RECT  0 22.8 0.084 22.824 ;
    END
  END i[26]
  PIN i[270]
    DIRECTION INPUT ;
    USE SIGNAL ;
    PORT
      LAYER M4 ;
        RECT  0 3.6 0.084 3.624 ;
    END
  END i[270]
  PIN i[271]
    DIRECTION INPUT ;
    USE SIGNAL ;
    PORT
      LAYER M4 ;
        RECT  0 3.696 0.084 3.72 ;
    END
  END i[271]
  PIN i[272]
    DIRECTION INPUT ;
    USE SIGNAL ;
    PORT
      LAYER M4 ;
        RECT  0 3.792 0.084 3.816 ;
    END
  END i[272]
  PIN i[273]
    DIRECTION INPUT ;
    USE SIGNAL ;
    PORT
      LAYER M4 ;
        RECT  0 3.888 0.084 3.912 ;
    END
  END i[273]
  PIN i[274]
    DIRECTION INPUT ;
    USE SIGNAL ;
    PORT
      LAYER M4 ;
        RECT  0 3.984 0.084 4.008 ;
    END
  END i[274]
  PIN i[275]
    DIRECTION INPUT ;
    USE SIGNAL ;
    PORT
      LAYER M4 ;
        RECT  0 4.08 0.084 4.104 ;
    END
  END i[275]
  PIN i[27]
    DIRECTION INPUT ;
    USE SIGNAL ;
    PORT
      LAYER M4 ;
        RECT  0 22.896 0.084 22.92 ;
    END
  END i[27]
  PIN i[28]
    DIRECTION INPUT ;
    USE SIGNAL ;
    PORT
      LAYER M4 ;
        RECT  0 22.992 0.084 23.016 ;
    END
  END i[28]
  PIN i[29]
    DIRECTION INPUT ;
    USE SIGNAL ;
    PORT
      LAYER M4 ;
        RECT  0 23.088 0.084 23.112 ;
    END
  END i[29]
  PIN i[2]
    DIRECTION INPUT ;
    USE SIGNAL ;
    PORT
      LAYER M4 ;
        RECT  0 20.496 0.084 20.52 ;
    END
  END i[2]
  PIN i[30]
    DIRECTION INPUT ;
    USE SIGNAL ;
    PORT
      LAYER M4 ;
        RECT  0 23.184 0.084 23.208 ;
    END
  END i[30]
  PIN i[31]
    DIRECTION INPUT ;
    USE SIGNAL ;
    PORT
      LAYER M4 ;
        RECT  0 23.28 0.084 23.304 ;
    END
  END i[31]
  PIN i[32]
    DIRECTION INPUT ;
    USE SIGNAL ;
    PORT
      LAYER M4 ;
        RECT  0 26.448 0.084 26.472 ;
    END
  END i[32]
  PIN i[33]
    DIRECTION INPUT ;
    USE SIGNAL ;
    PORT
      LAYER M4 ;
        RECT  0 26.544 0.084 26.568 ;
    END
  END i[33]
  PIN i[34]
    DIRECTION INPUT ;
    USE SIGNAL ;
    PORT
      LAYER M4 ;
        RECT  0 26.64 0.084 26.664 ;
    END
  END i[34]
  PIN i[35]
    DIRECTION INPUT ;
    USE SIGNAL ;
    PORT
      LAYER M4 ;
        RECT  0 26.736 0.084 26.76 ;
    END
  END i[35]
  PIN i[36]
    DIRECTION INPUT ;
    USE SIGNAL ;
    PORT
      LAYER M4 ;
        RECT  0 26.832 0.084 26.856 ;
    END
  END i[36]
  PIN i[37]
    DIRECTION INPUT ;
    USE SIGNAL ;
    PORT
      LAYER M4 ;
        RECT  0 26.928 0.084 26.952 ;
    END
  END i[37]
  PIN i[38]
    DIRECTION INPUT ;
    USE SIGNAL ;
    PORT
      LAYER M4 ;
        RECT  0 27.024 0.084 27.048 ;
    END
  END i[38]
  PIN i[39]
    DIRECTION INPUT ;
    USE SIGNAL ;
    PORT
      LAYER M4 ;
        RECT  0 27.12 0.084 27.144 ;
    END
  END i[39]
  PIN i[3]
    DIRECTION INPUT ;
    USE SIGNAL ;
    PORT
      LAYER M4 ;
        RECT  0 20.592 0.084 20.616 ;
    END
  END i[3]
  PIN i[40]
    DIRECTION INPUT ;
    USE SIGNAL ;
    PORT
      LAYER M4 ;
        RECT  0 27.216 0.084 27.24 ;
    END
  END i[40]
  PIN i[41]
    DIRECTION INPUT ;
    USE SIGNAL ;
    PORT
      LAYER M4 ;
        RECT  0 27.312 0.084 27.336 ;
    END
  END i[41]
  PIN i[42]
    DIRECTION INPUT ;
    USE SIGNAL ;
    PORT
      LAYER M4 ;
        RECT  0 27.408 0.084 27.432 ;
    END
  END i[42]
  PIN i[43]
    DIRECTION INPUT ;
    USE SIGNAL ;
    PORT
      LAYER M4 ;
        RECT  0 27.504 0.084 27.528 ;
    END
  END i[43]
  PIN i[44]
    DIRECTION INPUT ;
    USE SIGNAL ;
    PORT
      LAYER M4 ;
        RECT  0 27.6 0.084 27.624 ;
    END
  END i[44]
  PIN i[45]
    DIRECTION INPUT ;
    USE SIGNAL ;
    PORT
      LAYER M4 ;
        RECT  0 27.696 0.084 27.72 ;
    END
  END i[45]
  PIN i[46]
    DIRECTION INPUT ;
    USE SIGNAL ;
    PORT
      LAYER M4 ;
        RECT  0 27.792 0.084 27.816 ;
    END
  END i[46]
  PIN i[47]
    DIRECTION INPUT ;
    USE SIGNAL ;
    PORT
      LAYER M4 ;
        RECT  0 27.888 0.084 27.912 ;
    END
  END i[47]
  PIN i[48]
    DIRECTION INPUT ;
    USE SIGNAL ;
    PORT
      LAYER M4 ;
        RECT  0 27.984 0.084 28.008 ;
    END
  END i[48]
  PIN i[49]
    DIRECTION INPUT ;
    USE SIGNAL ;
    PORT
      LAYER M4 ;
        RECT  0 28.08 0.084 28.104 ;
    END
  END i[49]
  PIN i[4]
    DIRECTION INPUT ;
    USE SIGNAL ;
    PORT
      LAYER M4 ;
        RECT  0 20.688 0.084 20.712 ;
    END
  END i[4]
  PIN i[50]
    DIRECTION INPUT ;
    USE SIGNAL ;
    PORT
      LAYER M4 ;
        RECT  0 28.176 0.084 28.2 ;
    END
  END i[50]
  PIN i[51]
    DIRECTION INPUT ;
    USE SIGNAL ;
    PORT
      LAYER M4 ;
        RECT  0 28.272 0.084 28.296 ;
    END
  END i[51]
  PIN i[52]
    DIRECTION INPUT ;
    USE SIGNAL ;
    PORT
      LAYER M4 ;
        RECT  0 28.368 0.084 28.392 ;
    END
  END i[52]
  PIN i[53]
    DIRECTION INPUT ;
    USE SIGNAL ;
    PORT
      LAYER M4 ;
        RECT  0 28.464 0.084 28.488 ;
    END
  END i[53]
  PIN i[54]
    DIRECTION INPUT ;
    USE SIGNAL ;
    PORT
      LAYER M4 ;
        RECT  0 28.56 0.084 28.584 ;
    END
  END i[54]
  PIN i[55]
    DIRECTION INPUT ;
    USE SIGNAL ;
    PORT
      LAYER M4 ;
        RECT  0 28.656 0.084 28.68 ;
    END
  END i[55]
  PIN i[56]
    DIRECTION INPUT ;
    USE SIGNAL ;
    PORT
      LAYER M4 ;
        RECT  0 28.752 0.084 28.776 ;
    END
  END i[56]
  PIN i[57]
    DIRECTION INPUT ;
    USE SIGNAL ;
    PORT
      LAYER M4 ;
        RECT  0 28.848 0.084 28.872 ;
    END
  END i[57]
  PIN i[58]
    DIRECTION INPUT ;
    USE SIGNAL ;
    PORT
      LAYER M4 ;
        RECT  0 28.944 0.084 28.968 ;
    END
  END i[58]
  PIN i[59]
    DIRECTION INPUT ;
    USE SIGNAL ;
    PORT
      LAYER M4 ;
        RECT  0 29.04 0.084 29.064 ;
    END
  END i[59]
  PIN i[5]
    DIRECTION INPUT ;
    USE SIGNAL ;
    PORT
      LAYER M4 ;
        RECT  0 20.784 0.084 20.808 ;
    END
  END i[5]
  PIN i[60]
    DIRECTION INPUT ;
    USE SIGNAL ;
    PORT
      LAYER M4 ;
        RECT  0 29.136 0.084 29.16 ;
    END
  END i[60]
  PIN i[61]
    DIRECTION INPUT ;
    USE SIGNAL ;
    PORT
      LAYER M4 ;
        RECT  0 29.232 0.084 29.256 ;
    END
  END i[61]
  PIN i[62]
    DIRECTION INPUT ;
    USE SIGNAL ;
    PORT
      LAYER M4 ;
        RECT  0 29.328 0.084 29.352 ;
    END
  END i[62]
  PIN i[63]
    DIRECTION INPUT ;
    USE SIGNAL ;
    PORT
      LAYER M4 ;
        RECT  0 29.424 0.084 29.448 ;
    END
  END i[63]
  PIN i[64]
    DIRECTION INPUT ;
    USE SIGNAL ;
    PORT
      LAYER M4 ;
        RECT  0 23.376 0.084 23.4 ;
    END
  END i[64]
  PIN i[65]
    DIRECTION INPUT ;
    USE SIGNAL ;
    PORT
      LAYER M4 ;
        RECT  0 23.472 0.084 23.496 ;
    END
  END i[65]
  PIN i[66]
    DIRECTION INPUT ;
    USE SIGNAL ;
    PORT
      LAYER M4 ;
        RECT  0 23.568 0.084 23.592 ;
    END
  END i[66]
  PIN i[67]
    DIRECTION INPUT ;
    USE SIGNAL ;
    PORT
      LAYER M4 ;
        RECT  0 23.664 0.084 23.688 ;
    END
  END i[67]
  PIN i[68]
    DIRECTION INPUT ;
    USE SIGNAL ;
    PORT
      LAYER M4 ;
        RECT  0 23.76 0.084 23.784 ;
    END
  END i[68]
  PIN i[69]
    DIRECTION INPUT ;
    USE SIGNAL ;
    PORT
      LAYER M4 ;
        RECT  0 23.856 0.084 23.88 ;
    END
  END i[69]
  PIN i[6]
    DIRECTION INPUT ;
    USE SIGNAL ;
    PORT
      LAYER M4 ;
        RECT  0 20.88 0.084 20.904 ;
    END
  END i[6]
  PIN i[70]
    DIRECTION INPUT ;
    USE SIGNAL ;
    PORT
      LAYER M4 ;
        RECT  0 23.952 0.084 23.976 ;
    END
  END i[70]
  PIN i[71]
    DIRECTION INPUT ;
    USE SIGNAL ;
    PORT
      LAYER M4 ;
        RECT  0 24.048 0.084 24.072 ;
    END
  END i[71]
  PIN i[72]
    DIRECTION INPUT ;
    USE SIGNAL ;
    PORT
      LAYER M4 ;
        RECT  0 24.144 0.084 24.168 ;
    END
  END i[72]
  PIN i[73]
    DIRECTION INPUT ;
    USE SIGNAL ;
    PORT
      LAYER M4 ;
        RECT  0 24.24 0.084 24.264 ;
    END
  END i[73]
  PIN i[74]
    DIRECTION INPUT ;
    USE SIGNAL ;
    PORT
      LAYER M4 ;
        RECT  0 24.336 0.084 24.36 ;
    END
  END i[74]
  PIN i[75]
    DIRECTION INPUT ;
    USE SIGNAL ;
    PORT
      LAYER M4 ;
        RECT  0 24.432 0.084 24.456 ;
    END
  END i[75]
  PIN i[76]
    DIRECTION INPUT ;
    USE SIGNAL ;
    PORT
      LAYER M4 ;
        RECT  0 24.528 0.084 24.552 ;
    END
  END i[76]
  PIN i[77]
    DIRECTION INPUT ;
    USE SIGNAL ;
    PORT
      LAYER M4 ;
        RECT  0 24.624 0.084 24.648 ;
    END
  END i[77]
  PIN i[78]
    DIRECTION INPUT ;
    USE SIGNAL ;
    PORT
      LAYER M4 ;
        RECT  0 24.72 0.084 24.744 ;
    END
  END i[78]
  PIN i[79]
    DIRECTION INPUT ;
    USE SIGNAL ;
    PORT
      LAYER M4 ;
        RECT  0 24.816 0.084 24.84 ;
    END
  END i[79]
  PIN i[7]
    DIRECTION INPUT ;
    USE SIGNAL ;
    PORT
      LAYER M4 ;
        RECT  0 20.976 0.084 21 ;
    END
  END i[7]
  PIN i[80]
    DIRECTION INPUT ;
    USE SIGNAL ;
    PORT
      LAYER M4 ;
        RECT  0 24.912 0.084 24.936 ;
    END
  END i[80]
  PIN i[81]
    DIRECTION INPUT ;
    USE SIGNAL ;
    PORT
      LAYER M4 ;
        RECT  0 25.008 0.084 25.032 ;
    END
  END i[81]
  PIN i[82]
    DIRECTION INPUT ;
    USE SIGNAL ;
    PORT
      LAYER M4 ;
        RECT  0 25.104 0.084 25.128 ;
    END
  END i[82]
  PIN i[83]
    DIRECTION INPUT ;
    USE SIGNAL ;
    PORT
      LAYER M4 ;
        RECT  0 25.2 0.084 25.224 ;
    END
  END i[83]
  PIN i[84]
    DIRECTION INPUT ;
    USE SIGNAL ;
    PORT
      LAYER M4 ;
        RECT  0 25.296 0.084 25.32 ;
    END
  END i[84]
  PIN i[85]
    DIRECTION INPUT ;
    USE SIGNAL ;
    PORT
      LAYER M4 ;
        RECT  0 25.392 0.084 25.416 ;
    END
  END i[85]
  PIN i[86]
    DIRECTION INPUT ;
    USE SIGNAL ;
    PORT
      LAYER M4 ;
        RECT  0 25.488 0.084 25.512 ;
    END
  END i[86]
  PIN i[87]
    DIRECTION INPUT ;
    USE SIGNAL ;
    PORT
      LAYER M4 ;
        RECT  0 25.584 0.084 25.608 ;
    END
  END i[87]
  PIN i[88]
    DIRECTION INPUT ;
    USE SIGNAL ;
    PORT
      LAYER M4 ;
        RECT  0 25.68 0.084 25.704 ;
    END
  END i[88]
  PIN i[89]
    DIRECTION INPUT ;
    USE SIGNAL ;
    PORT
      LAYER M4 ;
        RECT  0 25.776 0.084 25.8 ;
    END
  END i[89]
  PIN i[8]
    DIRECTION INPUT ;
    USE SIGNAL ;
    PORT
      LAYER M4 ;
        RECT  0 21.072 0.084 21.096 ;
    END
  END i[8]
  PIN i[90]
    DIRECTION INPUT ;
    USE SIGNAL ;
    PORT
      LAYER M4 ;
        RECT  0 25.872 0.084 25.896 ;
    END
  END i[90]
  PIN i[91]
    DIRECTION INPUT ;
    USE SIGNAL ;
    PORT
      LAYER M4 ;
        RECT  0 25.968 0.084 25.992 ;
    END
  END i[91]
  PIN i[92]
    DIRECTION INPUT ;
    USE SIGNAL ;
    PORT
      LAYER M4 ;
        RECT  0 26.064 0.084 26.088 ;
    END
  END i[92]
  PIN i[93]
    DIRECTION INPUT ;
    USE SIGNAL ;
    PORT
      LAYER M4 ;
        RECT  0 26.16 0.084 26.184 ;
    END
  END i[93]
  PIN i[94]
    DIRECTION INPUT ;
    USE SIGNAL ;
    PORT
      LAYER M4 ;
        RECT  0 26.256 0.084 26.28 ;
    END
  END i[94]
  PIN i[95]
    DIRECTION INPUT ;
    USE SIGNAL ;
    PORT
      LAYER M4 ;
        RECT  0 26.352 0.084 26.376 ;
    END
  END i[95]
  PIN i[96]
    DIRECTION INPUT ;
    USE SIGNAL ;
    PORT
      LAYER M4 ;
        RECT  0 4.176 0.084 4.2 ;
    END
  END i[96]
  PIN i[97]
    DIRECTION INPUT ;
    USE SIGNAL ;
    PORT
      LAYER M4 ;
        RECT  0 4.272 0.084 4.296 ;
    END
  END i[97]
  PIN i[98]
    DIRECTION INPUT ;
    USE SIGNAL ;
    PORT
      LAYER M4 ;
        RECT  0 4.368 0.084 4.392 ;
    END
  END i[98]
  PIN i[99]
    DIRECTION INPUT ;
    USE SIGNAL ;
    PORT
      LAYER M4 ;
        RECT  0 4.464 0.084 4.488 ;
    END
  END i[99]
  PIN i[9]
    DIRECTION INPUT ;
    USE SIGNAL ;
    PORT
      LAYER M4 ;
        RECT  0 21.168 0.084 21.192 ;
    END
  END i[9]
  PIN o[0]
    DIRECTION OUTPUT ;
    USE SIGNAL ;
    PORT
      LAYER M4 ;
        RECT  23.676 9.936 23.76 9.96 ;
    END
  END o[0]
  PIN o[100]
    DIRECTION OUTPUT ;
    USE SIGNAL ;
    PORT
      LAYER M4 ;
        RECT  23.676 4.176 23.76 4.2 ;
    END
  END o[100]
  PIN o[101]
    DIRECTION OUTPUT ;
    USE SIGNAL ;
    PORT
      LAYER M4 ;
        RECT  23.676 4.272 23.76 4.296 ;
    END
  END o[101]
  PIN o[102]
    DIRECTION OUTPUT ;
    USE SIGNAL ;
    PORT
      LAYER M4 ;
        RECT  23.676 4.368 23.76 4.392 ;
    END
  END o[102]
  PIN o[103]
    DIRECTION OUTPUT ;
    USE SIGNAL ;
    PORT
      LAYER M4 ;
        RECT  23.676 4.464 23.76 4.488 ;
    END
  END o[103]
  PIN o[104]
    DIRECTION OUTPUT ;
    USE SIGNAL ;
    PORT
      LAYER M4 ;
        RECT  23.676 4.56 23.76 4.584 ;
    END
  END o[104]
  PIN o[105]
    DIRECTION OUTPUT ;
    USE SIGNAL ;
    PORT
      LAYER M4 ;
        RECT  23.676 4.656 23.76 4.68 ;
    END
  END o[105]
  PIN o[106]
    DIRECTION OUTPUT ;
    USE SIGNAL ;
    PORT
      LAYER M4 ;
        RECT  23.676 4.752 23.76 4.776 ;
    END
  END o[106]
  PIN o[107]
    DIRECTION OUTPUT ;
    USE SIGNAL ;
    PORT
      LAYER M4 ;
        RECT  23.676 4.848 23.76 4.872 ;
    END
  END o[107]
  PIN o[108]
    DIRECTION OUTPUT ;
    USE SIGNAL ;
    PORT
      LAYER M4 ;
        RECT  23.676 4.944 23.76 4.968 ;
    END
  END o[108]
  PIN o[109]
    DIRECTION OUTPUT ;
    USE SIGNAL ;
    PORT
      LAYER M4 ;
        RECT  23.676 5.04 23.76 5.064 ;
    END
  END o[109]
  PIN o[10]
    DIRECTION OUTPUT ;
    USE SIGNAL ;
    PORT
      LAYER M4 ;
        RECT  23.676 10.896 23.76 10.92 ;
    END
  END o[10]
  PIN o[110]
    DIRECTION OUTPUT ;
    USE SIGNAL ;
    PORT
      LAYER M4 ;
        RECT  23.676 5.136 23.76 5.16 ;
    END
  END o[110]
  PIN o[111]
    DIRECTION OUTPUT ;
    USE SIGNAL ;
    PORT
      LAYER M4 ;
        RECT  23.676 5.232 23.76 5.256 ;
    END
  END o[111]
  PIN o[112]
    DIRECTION OUTPUT ;
    USE SIGNAL ;
    PORT
      LAYER M4 ;
        RECT  23.676 5.328 23.76 5.352 ;
    END
  END o[112]
  PIN o[113]
    DIRECTION OUTPUT ;
    USE SIGNAL ;
    PORT
      LAYER M4 ;
        RECT  23.676 5.424 23.76 5.448 ;
    END
  END o[113]
  PIN o[114]
    DIRECTION OUTPUT ;
    USE SIGNAL ;
    PORT
      LAYER M4 ;
        RECT  23.676 5.52 23.76 5.544 ;
    END
  END o[114]
  PIN o[115]
    DIRECTION OUTPUT ;
    USE SIGNAL ;
    PORT
      LAYER M4 ;
        RECT  23.676 5.616 23.76 5.64 ;
    END
  END o[115]
  PIN o[116]
    DIRECTION OUTPUT ;
    USE SIGNAL ;
    PORT
      LAYER M4 ;
        RECT  23.676 5.712 23.76 5.736 ;
    END
  END o[116]
  PIN o[117]
    DIRECTION OUTPUT ;
    USE SIGNAL ;
    PORT
      LAYER M4 ;
        RECT  23.676 5.808 23.76 5.832 ;
    END
  END o[117]
  PIN o[118]
    DIRECTION OUTPUT ;
    USE SIGNAL ;
    PORT
      LAYER M4 ;
        RECT  23.676 5.904 23.76 5.928 ;
    END
  END o[118]
  PIN o[119]
    DIRECTION OUTPUT ;
    USE SIGNAL ;
    PORT
      LAYER M4 ;
        RECT  23.676 6 23.76 6.024 ;
    END
  END o[119]
  PIN o[11]
    DIRECTION OUTPUT ;
    USE SIGNAL ;
    PORT
      LAYER M4 ;
        RECT  23.676 10.992 23.76 11.016 ;
    END
  END o[11]
  PIN o[120]
    DIRECTION OUTPUT ;
    USE SIGNAL ;
    PORT
      LAYER M4 ;
        RECT  23.676 6.096 23.76 6.12 ;
    END
  END o[120]
  PIN o[121]
    DIRECTION OUTPUT ;
    USE SIGNAL ;
    PORT
      LAYER M4 ;
        RECT  23.676 6.192 23.76 6.216 ;
    END
  END o[121]
  PIN o[122]
    DIRECTION OUTPUT ;
    USE SIGNAL ;
    PORT
      LAYER M4 ;
        RECT  23.676 6.288 23.76 6.312 ;
    END
  END o[122]
  PIN o[123]
    DIRECTION OUTPUT ;
    USE SIGNAL ;
    PORT
      LAYER M4 ;
        RECT  23.676 6.384 23.76 6.408 ;
    END
  END o[123]
  PIN o[124]
    DIRECTION OUTPUT ;
    USE SIGNAL ;
    PORT
      LAYER M4 ;
        RECT  23.676 6.48 23.76 6.504 ;
    END
  END o[124]
  PIN o[125]
    DIRECTION OUTPUT ;
    USE SIGNAL ;
    PORT
      LAYER M4 ;
        RECT  23.676 6.576 23.76 6.6 ;
    END
  END o[125]
  PIN o[126]
    DIRECTION OUTPUT ;
    USE SIGNAL ;
    PORT
      LAYER M4 ;
        RECT  23.676 6.672 23.76 6.696 ;
    END
  END o[126]
  PIN o[127]
    DIRECTION OUTPUT ;
    USE SIGNAL ;
    PORT
      LAYER M4 ;
        RECT  23.676 6.768 23.76 6.792 ;
    END
  END o[127]
  PIN o[128]
    DIRECTION OUTPUT ;
    USE SIGNAL ;
    PORT
      LAYER M4 ;
        RECT  23.676 0.72 23.76 0.744 ;
    END
  END o[128]
  PIN o[129]
    DIRECTION OUTPUT ;
    USE SIGNAL ;
    PORT
      LAYER M4 ;
        RECT  23.676 0.816 23.76 0.84 ;
    END
  END o[129]
  PIN o[12]
    DIRECTION OUTPUT ;
    USE SIGNAL ;
    PORT
      LAYER M4 ;
        RECT  23.676 11.088 23.76 11.112 ;
    END
  END o[12]
  PIN o[130]
    DIRECTION OUTPUT ;
    USE SIGNAL ;
    PORT
      LAYER M4 ;
        RECT  23.676 0.912 23.76 0.936 ;
    END
  END o[130]
  PIN o[131]
    DIRECTION OUTPUT ;
    USE SIGNAL ;
    PORT
      LAYER M4 ;
        RECT  23.676 1.008 23.76 1.032 ;
    END
  END o[131]
  PIN o[132]
    DIRECTION OUTPUT ;
    USE SIGNAL ;
    PORT
      LAYER M4 ;
        RECT  23.676 1.104 23.76 1.128 ;
    END
  END o[132]
  PIN o[133]
    DIRECTION OUTPUT ;
    USE SIGNAL ;
    PORT
      LAYER M4 ;
        RECT  23.676 1.2 23.76 1.224 ;
    END
  END o[133]
  PIN o[134]
    DIRECTION OUTPUT ;
    USE SIGNAL ;
    PORT
      LAYER M4 ;
        RECT  23.676 1.296 23.76 1.32 ;
    END
  END o[134]
  PIN o[135]
    DIRECTION OUTPUT ;
    USE SIGNAL ;
    PORT
      LAYER M4 ;
        RECT  23.676 1.392 23.76 1.416 ;
    END
  END o[135]
  PIN o[136]
    DIRECTION OUTPUT ;
    USE SIGNAL ;
    PORT
      LAYER M4 ;
        RECT  23.676 1.488 23.76 1.512 ;
    END
  END o[136]
  PIN o[137]
    DIRECTION OUTPUT ;
    USE SIGNAL ;
    PORT
      LAYER M4 ;
        RECT  23.676 1.584 23.76 1.608 ;
    END
  END o[137]
  PIN o[138]
    DIRECTION OUTPUT ;
    USE SIGNAL ;
    PORT
      LAYER M4 ;
        RECT  23.676 1.68 23.76 1.704 ;
    END
  END o[138]
  PIN o[139]
    DIRECTION OUTPUT ;
    USE SIGNAL ;
    PORT
      LAYER M4 ;
        RECT  23.676 1.776 23.76 1.8 ;
    END
  END o[139]
  PIN o[13]
    DIRECTION OUTPUT ;
    USE SIGNAL ;
    PORT
      LAYER M4 ;
        RECT  23.676 11.184 23.76 11.208 ;
    END
  END o[13]
  PIN o[140]
    DIRECTION OUTPUT ;
    USE SIGNAL ;
    PORT
      LAYER M4 ;
        RECT  23.676 1.872 23.76 1.896 ;
    END
  END o[140]
  PIN o[141]
    DIRECTION OUTPUT ;
    USE SIGNAL ;
    PORT
      LAYER M4 ;
        RECT  23.676 1.968 23.76 1.992 ;
    END
  END o[141]
  PIN o[142]
    DIRECTION OUTPUT ;
    USE SIGNAL ;
    PORT
      LAYER M4 ;
        RECT  23.676 2.064 23.76 2.088 ;
    END
  END o[142]
  PIN o[143]
    DIRECTION OUTPUT ;
    USE SIGNAL ;
    PORT
      LAYER M4 ;
        RECT  23.676 2.16 23.76 2.184 ;
    END
  END o[143]
  PIN o[144]
    DIRECTION OUTPUT ;
    USE SIGNAL ;
    PORT
      LAYER M4 ;
        RECT  23.676 2.256 23.76 2.28 ;
    END
  END o[144]
  PIN o[145]
    DIRECTION OUTPUT ;
    USE SIGNAL ;
    PORT
      LAYER M4 ;
        RECT  23.676 2.352 23.76 2.376 ;
    END
  END o[145]
  PIN o[146]
    DIRECTION OUTPUT ;
    USE SIGNAL ;
    PORT
      LAYER M4 ;
        RECT  23.676 2.448 23.76 2.472 ;
    END
  END o[146]
  PIN o[147]
    DIRECTION OUTPUT ;
    USE SIGNAL ;
    PORT
      LAYER M4 ;
        RECT  23.676 2.544 23.76 2.568 ;
    END
  END o[147]
  PIN o[148]
    DIRECTION OUTPUT ;
    USE SIGNAL ;
    PORT
      LAYER M4 ;
        RECT  23.676 2.64 23.76 2.664 ;
    END
  END o[148]
  PIN o[149]
    DIRECTION OUTPUT ;
    USE SIGNAL ;
    PORT
      LAYER M4 ;
        RECT  23.676 2.736 23.76 2.76 ;
    END
  END o[149]
  PIN o[14]
    DIRECTION OUTPUT ;
    USE SIGNAL ;
    PORT
      LAYER M4 ;
        RECT  23.676 11.28 23.76 11.304 ;
    END
  END o[14]
  PIN o[150]
    DIRECTION OUTPUT ;
    USE SIGNAL ;
    PORT
      LAYER M4 ;
        RECT  23.676 2.832 23.76 2.856 ;
    END
  END o[150]
  PIN o[151]
    DIRECTION OUTPUT ;
    USE SIGNAL ;
    PORT
      LAYER M4 ;
        RECT  23.676 2.928 23.76 2.952 ;
    END
  END o[151]
  PIN o[152]
    DIRECTION OUTPUT ;
    USE SIGNAL ;
    PORT
      LAYER M4 ;
        RECT  23.676 3.024 23.76 3.048 ;
    END
  END o[152]
  PIN o[153]
    DIRECTION OUTPUT ;
    USE SIGNAL ;
    PORT
      LAYER M4 ;
        RECT  23.676 3.12 23.76 3.144 ;
    END
  END o[153]
  PIN o[154]
    DIRECTION OUTPUT ;
    USE SIGNAL ;
    PORT
      LAYER M4 ;
        RECT  23.676 3.216 23.76 3.24 ;
    END
  END o[154]
  PIN o[155]
    DIRECTION OUTPUT ;
    USE SIGNAL ;
    PORT
      LAYER M4 ;
        RECT  23.676 3.312 23.76 3.336 ;
    END
  END o[155]
  PIN o[156]
    DIRECTION OUTPUT ;
    USE SIGNAL ;
    PORT
      LAYER M4 ;
        RECT  23.676 3.408 23.76 3.432 ;
    END
  END o[156]
  PIN o[157]
    DIRECTION OUTPUT ;
    USE SIGNAL ;
    PORT
      LAYER M4 ;
        RECT  23.676 3.504 23.76 3.528 ;
    END
  END o[157]
  PIN o[158]
    DIRECTION OUTPUT ;
    USE SIGNAL ;
    PORT
      LAYER M4 ;
        RECT  23.676 3.6 23.76 3.624 ;
    END
  END o[158]
  PIN o[159]
    DIRECTION OUTPUT ;
    USE SIGNAL ;
    PORT
      LAYER M4 ;
        RECT  23.676 3.696 23.76 3.72 ;
    END
  END o[159]
  PIN o[15]
    DIRECTION OUTPUT ;
    USE SIGNAL ;
    PORT
      LAYER M4 ;
        RECT  23.676 11.376 23.76 11.4 ;
    END
  END o[15]
  PIN o[160]
    DIRECTION OUTPUT ;
    USE SIGNAL ;
    PORT
      LAYER M4 ;
        RECT  23.676 16.08 23.76 16.104 ;
    END
  END o[160]
  PIN o[161]
    DIRECTION OUTPUT ;
    USE SIGNAL ;
    PORT
      LAYER M4 ;
        RECT  23.676 16.176 23.76 16.2 ;
    END
  END o[161]
  PIN o[162]
    DIRECTION OUTPUT ;
    USE SIGNAL ;
    PORT
      LAYER M4 ;
        RECT  23.676 16.272 23.76 16.296 ;
    END
  END o[162]
  PIN o[163]
    DIRECTION OUTPUT ;
    USE SIGNAL ;
    PORT
      LAYER M4 ;
        RECT  23.676 16.368 23.76 16.392 ;
    END
  END o[163]
  PIN o[164]
    DIRECTION OUTPUT ;
    USE SIGNAL ;
    PORT
      LAYER M4 ;
        RECT  23.676 16.464 23.76 16.488 ;
    END
  END o[164]
  PIN o[165]
    DIRECTION OUTPUT ;
    USE SIGNAL ;
    PORT
      LAYER M4 ;
        RECT  23.676 16.56 23.76 16.584 ;
    END
  END o[165]
  PIN o[166]
    DIRECTION OUTPUT ;
    USE SIGNAL ;
    PORT
      LAYER M4 ;
        RECT  23.676 16.656 23.76 16.68 ;
    END
  END o[166]
  PIN o[167]
    DIRECTION OUTPUT ;
    USE SIGNAL ;
    PORT
      LAYER M4 ;
        RECT  23.676 16.752 23.76 16.776 ;
    END
  END o[167]
  PIN o[168]
    DIRECTION OUTPUT ;
    USE SIGNAL ;
    PORT
      LAYER M4 ;
        RECT  23.676 16.848 23.76 16.872 ;
    END
  END o[168]
  PIN o[169]
    DIRECTION OUTPUT ;
    USE SIGNAL ;
    PORT
      LAYER M4 ;
        RECT  23.676 16.944 23.76 16.968 ;
    END
  END o[169]
  PIN o[16]
    DIRECTION OUTPUT ;
    USE SIGNAL ;
    PORT
      LAYER M4 ;
        RECT  23.676 11.472 23.76 11.496 ;
    END
  END o[16]
  PIN o[170]
    DIRECTION OUTPUT ;
    USE SIGNAL ;
    PORT
      LAYER M4 ;
        RECT  23.676 17.04 23.76 17.064 ;
    END
  END o[170]
  PIN o[171]
    DIRECTION OUTPUT ;
    USE SIGNAL ;
    PORT
      LAYER M4 ;
        RECT  23.676 17.136 23.76 17.16 ;
    END
  END o[171]
  PIN o[172]
    DIRECTION OUTPUT ;
    USE SIGNAL ;
    PORT
      LAYER M4 ;
        RECT  23.676 17.232 23.76 17.256 ;
    END
  END o[172]
  PIN o[173]
    DIRECTION OUTPUT ;
    USE SIGNAL ;
    PORT
      LAYER M4 ;
        RECT  23.676 17.328 23.76 17.352 ;
    END
  END o[173]
  PIN o[174]
    DIRECTION OUTPUT ;
    USE SIGNAL ;
    PORT
      LAYER M4 ;
        RECT  23.676 17.424 23.76 17.448 ;
    END
  END o[174]
  PIN o[175]
    DIRECTION OUTPUT ;
    USE SIGNAL ;
    PORT
      LAYER M4 ;
        RECT  23.676 17.52 23.76 17.544 ;
    END
  END o[175]
  PIN o[176]
    DIRECTION OUTPUT ;
    USE SIGNAL ;
    PORT
      LAYER M4 ;
        RECT  23.676 17.616 23.76 17.64 ;
    END
  END o[176]
  PIN o[177]
    DIRECTION OUTPUT ;
    USE SIGNAL ;
    PORT
      LAYER M4 ;
        RECT  23.676 17.712 23.76 17.736 ;
    END
  END o[177]
  PIN o[178]
    DIRECTION OUTPUT ;
    USE SIGNAL ;
    PORT
      LAYER M4 ;
        RECT  23.676 17.808 23.76 17.832 ;
    END
  END o[178]
  PIN o[179]
    DIRECTION OUTPUT ;
    USE SIGNAL ;
    PORT
      LAYER M4 ;
        RECT  23.676 17.904 23.76 17.928 ;
    END
  END o[179]
  PIN o[17]
    DIRECTION OUTPUT ;
    USE SIGNAL ;
    PORT
      LAYER M4 ;
        RECT  23.676 11.568 23.76 11.592 ;
    END
  END o[17]
  PIN o[180]
    DIRECTION OUTPUT ;
    USE SIGNAL ;
    PORT
      LAYER M4 ;
        RECT  23.676 18 23.76 18.024 ;
    END
  END o[180]
  PIN o[181]
    DIRECTION OUTPUT ;
    USE SIGNAL ;
    PORT
      LAYER M4 ;
        RECT  23.676 18.096 23.76 18.12 ;
    END
  END o[181]
  PIN o[182]
    DIRECTION OUTPUT ;
    USE SIGNAL ;
    PORT
      LAYER M4 ;
        RECT  23.676 18.192 23.76 18.216 ;
    END
  END o[182]
  PIN o[183]
    DIRECTION OUTPUT ;
    USE SIGNAL ;
    PORT
      LAYER M4 ;
        RECT  23.676 18.288 23.76 18.312 ;
    END
  END o[183]
  PIN o[184]
    DIRECTION OUTPUT ;
    USE SIGNAL ;
    PORT
      LAYER M4 ;
        RECT  23.676 18.384 23.76 18.408 ;
    END
  END o[184]
  PIN o[185]
    DIRECTION OUTPUT ;
    USE SIGNAL ;
    PORT
      LAYER M4 ;
        RECT  23.676 18.48 23.76 18.504 ;
    END
  END o[185]
  PIN o[186]
    DIRECTION OUTPUT ;
    USE SIGNAL ;
    PORT
      LAYER M4 ;
        RECT  23.676 18.576 23.76 18.6 ;
    END
  END o[186]
  PIN o[187]
    DIRECTION OUTPUT ;
    USE SIGNAL ;
    PORT
      LAYER M4 ;
        RECT  23.676 18.672 23.76 18.696 ;
    END
  END o[187]
  PIN o[188]
    DIRECTION OUTPUT ;
    USE SIGNAL ;
    PORT
      LAYER M4 ;
        RECT  23.676 18.768 23.76 18.792 ;
    END
  END o[188]
  PIN o[189]
    DIRECTION OUTPUT ;
    USE SIGNAL ;
    PORT
      LAYER M4 ;
        RECT  23.676 18.864 23.76 18.888 ;
    END
  END o[189]
  PIN o[18]
    DIRECTION OUTPUT ;
    USE SIGNAL ;
    PORT
      LAYER M4 ;
        RECT  23.676 11.664 23.76 11.688 ;
    END
  END o[18]
  PIN o[190]
    DIRECTION OUTPUT ;
    USE SIGNAL ;
    PORT
      LAYER M4 ;
        RECT  23.676 18.96 23.76 18.984 ;
    END
  END o[190]
  PIN o[191]
    DIRECTION OUTPUT ;
    USE SIGNAL ;
    PORT
      LAYER M4 ;
        RECT  23.676 19.056 23.76 19.08 ;
    END
  END o[191]
  PIN o[192]
    DIRECTION OUTPUT ;
    USE SIGNAL ;
    PORT
      LAYER M4 ;
        RECT  23.676 19.92 23.76 19.944 ;
    END
  END o[192]
  PIN o[193]
    DIRECTION OUTPUT ;
    USE SIGNAL ;
    PORT
      LAYER M4 ;
        RECT  23.676 20.016 23.76 20.04 ;
    END
  END o[193]
  PIN o[194]
    DIRECTION OUTPUT ;
    USE SIGNAL ;
    PORT
      LAYER M4 ;
        RECT  23.676 20.112 23.76 20.136 ;
    END
  END o[194]
  PIN o[195]
    DIRECTION OUTPUT ;
    USE SIGNAL ;
    PORT
      LAYER M4 ;
        RECT  23.676 20.208 23.76 20.232 ;
    END
  END o[195]
  PIN o[196]
    DIRECTION OUTPUT ;
    USE SIGNAL ;
    PORT
      LAYER M4 ;
        RECT  23.676 20.304 23.76 20.328 ;
    END
  END o[196]
  PIN o[197]
    DIRECTION OUTPUT ;
    USE SIGNAL ;
    PORT
      LAYER M4 ;
        RECT  23.676 20.4 23.76 20.424 ;
    END
  END o[197]
  PIN o[198]
    DIRECTION OUTPUT ;
    USE SIGNAL ;
    PORT
      LAYER M4 ;
        RECT  23.676 20.496 23.76 20.52 ;
    END
  END o[198]
  PIN o[199]
    DIRECTION OUTPUT ;
    USE SIGNAL ;
    PORT
      LAYER M4 ;
        RECT  23.676 20.592 23.76 20.616 ;
    END
  END o[199]
  PIN o[19]
    DIRECTION OUTPUT ;
    USE SIGNAL ;
    PORT
      LAYER M4 ;
        RECT  23.676 11.76 23.76 11.784 ;
    END
  END o[19]
  PIN o[1]
    DIRECTION OUTPUT ;
    USE SIGNAL ;
    PORT
      LAYER M4 ;
        RECT  23.676 10.032 23.76 10.056 ;
    END
  END o[1]
  PIN o[200]
    DIRECTION OUTPUT ;
    USE SIGNAL ;
    PORT
      LAYER M4 ;
        RECT  23.676 20.688 23.76 20.712 ;
    END
  END o[200]
  PIN o[201]
    DIRECTION OUTPUT ;
    USE SIGNAL ;
    PORT
      LAYER M4 ;
        RECT  23.676 20.784 23.76 20.808 ;
    END
  END o[201]
  PIN o[202]
    DIRECTION OUTPUT ;
    USE SIGNAL ;
    PORT
      LAYER M4 ;
        RECT  23.676 20.88 23.76 20.904 ;
    END
  END o[202]
  PIN o[203]
    DIRECTION OUTPUT ;
    USE SIGNAL ;
    PORT
      LAYER M4 ;
        RECT  23.676 20.976 23.76 21 ;
    END
  END o[203]
  PIN o[204]
    DIRECTION OUTPUT ;
    USE SIGNAL ;
    PORT
      LAYER M4 ;
        RECT  23.676 21.072 23.76 21.096 ;
    END
  END o[204]
  PIN o[205]
    DIRECTION OUTPUT ;
    USE SIGNAL ;
    PORT
      LAYER M4 ;
        RECT  23.676 21.168 23.76 21.192 ;
    END
  END o[205]
  PIN o[206]
    DIRECTION OUTPUT ;
    USE SIGNAL ;
    PORT
      LAYER M4 ;
        RECT  23.676 21.264 23.76 21.288 ;
    END
  END o[206]
  PIN o[207]
    DIRECTION OUTPUT ;
    USE SIGNAL ;
    PORT
      LAYER M4 ;
        RECT  23.676 21.36 23.76 21.384 ;
    END
  END o[207]
  PIN o[208]
    DIRECTION OUTPUT ;
    USE SIGNAL ;
    PORT
      LAYER M4 ;
        RECT  23.676 21.456 23.76 21.48 ;
    END
  END o[208]
  PIN o[209]
    DIRECTION OUTPUT ;
    USE SIGNAL ;
    PORT
      LAYER M4 ;
        RECT  23.676 21.552 23.76 21.576 ;
    END
  END o[209]
  PIN o[20]
    DIRECTION OUTPUT ;
    USE SIGNAL ;
    PORT
      LAYER M4 ;
        RECT  23.676 11.856 23.76 11.88 ;
    END
  END o[20]
  PIN o[210]
    DIRECTION OUTPUT ;
    USE SIGNAL ;
    PORT
      LAYER M4 ;
        RECT  23.676 21.648 23.76 21.672 ;
    END
  END o[210]
  PIN o[211]
    DIRECTION OUTPUT ;
    USE SIGNAL ;
    PORT
      LAYER M4 ;
        RECT  23.676 21.744 23.76 21.768 ;
    END
  END o[211]
  PIN o[212]
    DIRECTION OUTPUT ;
    USE SIGNAL ;
    PORT
      LAYER M4 ;
        RECT  23.676 21.84 23.76 21.864 ;
    END
  END o[212]
  PIN o[213]
    DIRECTION OUTPUT ;
    USE SIGNAL ;
    PORT
      LAYER M4 ;
        RECT  23.676 21.936 23.76 21.96 ;
    END
  END o[213]
  PIN o[214]
    DIRECTION OUTPUT ;
    USE SIGNAL ;
    PORT
      LAYER M4 ;
        RECT  23.676 22.032 23.76 22.056 ;
    END
  END o[214]
  PIN o[215]
    DIRECTION OUTPUT ;
    USE SIGNAL ;
    PORT
      LAYER M4 ;
        RECT  23.676 22.128 23.76 22.152 ;
    END
  END o[215]
  PIN o[216]
    DIRECTION OUTPUT ;
    USE SIGNAL ;
    PORT
      LAYER M4 ;
        RECT  23.676 22.224 23.76 22.248 ;
    END
  END o[216]
  PIN o[217]
    DIRECTION OUTPUT ;
    USE SIGNAL ;
    PORT
      LAYER M4 ;
        RECT  23.676 22.32 23.76 22.344 ;
    END
  END o[217]
  PIN o[218]
    DIRECTION OUTPUT ;
    USE SIGNAL ;
    PORT
      LAYER M4 ;
        RECT  23.676 22.416 23.76 22.44 ;
    END
  END o[218]
  PIN o[219]
    DIRECTION OUTPUT ;
    USE SIGNAL ;
    PORT
      LAYER M4 ;
        RECT  23.676 22.512 23.76 22.536 ;
    END
  END o[219]
  PIN o[21]
    DIRECTION OUTPUT ;
    USE SIGNAL ;
    PORT
      LAYER M4 ;
        RECT  23.676 11.952 23.76 11.976 ;
    END
  END o[21]
  PIN o[220]
    DIRECTION OUTPUT ;
    USE SIGNAL ;
    PORT
      LAYER M4 ;
        RECT  23.676 22.608 23.76 22.632 ;
    END
  END o[220]
  PIN o[221]
    DIRECTION OUTPUT ;
    USE SIGNAL ;
    PORT
      LAYER M4 ;
        RECT  23.676 22.704 23.76 22.728 ;
    END
  END o[221]
  PIN o[222]
    DIRECTION OUTPUT ;
    USE SIGNAL ;
    PORT
      LAYER M4 ;
        RECT  23.676 22.8 23.76 22.824 ;
    END
  END o[222]
  PIN o[223]
    DIRECTION OUTPUT ;
    USE SIGNAL ;
    PORT
      LAYER M4 ;
        RECT  23.676 22.896 23.76 22.92 ;
    END
  END o[223]
  PIN o[224]
    DIRECTION OUTPUT ;
    USE SIGNAL ;
    PORT
      LAYER M4 ;
        RECT  23.676 22.992 23.76 23.016 ;
    END
  END o[224]
  PIN o[225]
    DIRECTION OUTPUT ;
    USE SIGNAL ;
    PORT
      LAYER M4 ;
        RECT  23.676 23.088 23.76 23.112 ;
    END
  END o[225]
  PIN o[226]
    DIRECTION OUTPUT ;
    USE SIGNAL ;
    PORT
      LAYER M4 ;
        RECT  23.676 23.184 23.76 23.208 ;
    END
  END o[226]
  PIN o[227]
    DIRECTION OUTPUT ;
    USE SIGNAL ;
    PORT
      LAYER M4 ;
        RECT  23.676 23.28 23.76 23.304 ;
    END
  END o[227]
  PIN o[228]
    DIRECTION OUTPUT ;
    USE SIGNAL ;
    PORT
      LAYER M4 ;
        RECT  23.676 23.376 23.76 23.4 ;
    END
  END o[228]
  PIN o[229]
    DIRECTION OUTPUT ;
    USE SIGNAL ;
    PORT
      LAYER M4 ;
        RECT  23.676 23.472 23.76 23.496 ;
    END
  END o[229]
  PIN o[22]
    DIRECTION OUTPUT ;
    USE SIGNAL ;
    PORT
      LAYER M4 ;
        RECT  23.676 12.048 23.76 12.072 ;
    END
  END o[22]
  PIN o[230]
    DIRECTION OUTPUT ;
    USE SIGNAL ;
    PORT
      LAYER M4 ;
        RECT  23.676 23.568 23.76 23.592 ;
    END
  END o[230]
  PIN o[231]
    DIRECTION OUTPUT ;
    USE SIGNAL ;
    PORT
      LAYER M4 ;
        RECT  23.676 23.664 23.76 23.688 ;
    END
  END o[231]
  PIN o[232]
    DIRECTION OUTPUT ;
    USE SIGNAL ;
    PORT
      LAYER M4 ;
        RECT  23.676 23.76 23.76 23.784 ;
    END
  END o[232]
  PIN o[233]
    DIRECTION OUTPUT ;
    USE SIGNAL ;
    PORT
      LAYER M4 ;
        RECT  23.676 23.856 23.76 23.88 ;
    END
  END o[233]
  PIN o[234]
    DIRECTION OUTPUT ;
    USE SIGNAL ;
    PORT
      LAYER M4 ;
        RECT  23.676 23.952 23.76 23.976 ;
    END
  END o[234]
  PIN o[235]
    DIRECTION OUTPUT ;
    USE SIGNAL ;
    PORT
      LAYER M4 ;
        RECT  23.676 24.048 23.76 24.072 ;
    END
  END o[235]
  PIN o[236]
    DIRECTION OUTPUT ;
    USE SIGNAL ;
    PORT
      LAYER M4 ;
        RECT  23.676 24.144 23.76 24.168 ;
    END
  END o[236]
  PIN o[237]
    DIRECTION OUTPUT ;
    USE SIGNAL ;
    PORT
      LAYER M4 ;
        RECT  23.676 24.24 23.76 24.264 ;
    END
  END o[237]
  PIN o[238]
    DIRECTION OUTPUT ;
    USE SIGNAL ;
    PORT
      LAYER M4 ;
        RECT  23.676 24.336 23.76 24.36 ;
    END
  END o[238]
  PIN o[239]
    DIRECTION OUTPUT ;
    USE SIGNAL ;
    PORT
      LAYER M4 ;
        RECT  23.676 24.432 23.76 24.456 ;
    END
  END o[239]
  PIN o[23]
    DIRECTION OUTPUT ;
    USE SIGNAL ;
    PORT
      LAYER M4 ;
        RECT  23.676 12.144 23.76 12.168 ;
    END
  END o[23]
  PIN o[240]
    DIRECTION OUTPUT ;
    USE SIGNAL ;
    PORT
      LAYER M4 ;
        RECT  23.676 24.528 23.76 24.552 ;
    END
  END o[240]
  PIN o[241]
    DIRECTION OUTPUT ;
    USE SIGNAL ;
    PORT
      LAYER M4 ;
        RECT  23.676 24.624 23.76 24.648 ;
    END
  END o[241]
  PIN o[242]
    DIRECTION OUTPUT ;
    USE SIGNAL ;
    PORT
      LAYER M4 ;
        RECT  23.676 24.72 23.76 24.744 ;
    END
  END o[242]
  PIN o[243]
    DIRECTION OUTPUT ;
    USE SIGNAL ;
    PORT
      LAYER M4 ;
        RECT  23.676 24.816 23.76 24.84 ;
    END
  END o[243]
  PIN o[244]
    DIRECTION OUTPUT ;
    USE SIGNAL ;
    PORT
      LAYER M4 ;
        RECT  23.676 24.912 23.76 24.936 ;
    END
  END o[244]
  PIN o[245]
    DIRECTION OUTPUT ;
    USE SIGNAL ;
    PORT
      LAYER M4 ;
        RECT  23.676 25.008 23.76 25.032 ;
    END
  END o[245]
  PIN o[246]
    DIRECTION OUTPUT ;
    USE SIGNAL ;
    PORT
      LAYER M4 ;
        RECT  23.676 25.104 23.76 25.128 ;
    END
  END o[246]
  PIN o[247]
    DIRECTION OUTPUT ;
    USE SIGNAL ;
    PORT
      LAYER M4 ;
        RECT  23.676 25.2 23.76 25.224 ;
    END
  END o[247]
  PIN o[248]
    DIRECTION OUTPUT ;
    USE SIGNAL ;
    PORT
      LAYER M4 ;
        RECT  23.676 25.296 23.76 25.32 ;
    END
  END o[248]
  PIN o[249]
    DIRECTION OUTPUT ;
    USE SIGNAL ;
    PORT
      LAYER M4 ;
        RECT  23.676 25.392 23.76 25.416 ;
    END
  END o[249]
  PIN o[24]
    DIRECTION OUTPUT ;
    USE SIGNAL ;
    PORT
      LAYER M4 ;
        RECT  23.676 12.24 23.76 12.264 ;
    END
  END o[24]
  PIN o[250]
    DIRECTION OUTPUT ;
    USE SIGNAL ;
    PORT
      LAYER M4 ;
        RECT  23.676 25.488 23.76 25.512 ;
    END
  END o[250]
  PIN o[251]
    DIRECTION OUTPUT ;
    USE SIGNAL ;
    PORT
      LAYER M4 ;
        RECT  23.676 25.584 23.76 25.608 ;
    END
  END o[251]
  PIN o[252]
    DIRECTION OUTPUT ;
    USE SIGNAL ;
    PORT
      LAYER M4 ;
        RECT  23.676 25.68 23.76 25.704 ;
    END
  END o[252]
  PIN o[253]
    DIRECTION OUTPUT ;
    USE SIGNAL ;
    PORT
      LAYER M4 ;
        RECT  23.676 25.776 23.76 25.8 ;
    END
  END o[253]
  PIN o[254]
    DIRECTION OUTPUT ;
    USE SIGNAL ;
    PORT
      LAYER M4 ;
        RECT  23.676 25.872 23.76 25.896 ;
    END
  END o[254]
  PIN o[255]
    DIRECTION OUTPUT ;
    USE SIGNAL ;
    PORT
      LAYER M4 ;
        RECT  23.676 25.968 23.76 25.992 ;
    END
  END o[255]
  PIN o[256]
    DIRECTION OUTPUT ;
    USE SIGNAL ;
    PORT
      LAYER M4 ;
        RECT  23.676 26.064 23.76 26.088 ;
    END
  END o[256]
  PIN o[257]
    DIRECTION OUTPUT ;
    USE SIGNAL ;
    PORT
      LAYER M4 ;
        RECT  23.676 26.16 23.76 26.184 ;
    END
  END o[257]
  PIN o[258]
    DIRECTION OUTPUT ;
    USE SIGNAL ;
    PORT
      LAYER M4 ;
        RECT  23.676 26.256 23.76 26.28 ;
    END
  END o[258]
  PIN o[259]
    DIRECTION OUTPUT ;
    USE SIGNAL ;
    PORT
      LAYER M4 ;
        RECT  23.676 26.352 23.76 26.376 ;
    END
  END o[259]
  PIN o[25]
    DIRECTION OUTPUT ;
    USE SIGNAL ;
    PORT
      LAYER M4 ;
        RECT  23.676 12.336 23.76 12.36 ;
    END
  END o[25]
  PIN o[260]
    DIRECTION OUTPUT ;
    USE SIGNAL ;
    PORT
      LAYER M4 ;
        RECT  23.676 26.448 23.76 26.472 ;
    END
  END o[260]
  PIN o[261]
    DIRECTION OUTPUT ;
    USE SIGNAL ;
    PORT
      LAYER M4 ;
        RECT  23.676 26.544 23.76 26.568 ;
    END
  END o[261]
  PIN o[262]
    DIRECTION OUTPUT ;
    USE SIGNAL ;
    PORT
      LAYER M4 ;
        RECT  23.676 26.64 23.76 26.664 ;
    END
  END o[262]
  PIN o[263]
    DIRECTION OUTPUT ;
    USE SIGNAL ;
    PORT
      LAYER M4 ;
        RECT  23.676 26.736 23.76 26.76 ;
    END
  END o[263]
  PIN o[264]
    DIRECTION OUTPUT ;
    USE SIGNAL ;
    PORT
      LAYER M4 ;
        RECT  23.676 26.832 23.76 26.856 ;
    END
  END o[264]
  PIN o[265]
    DIRECTION OUTPUT ;
    USE SIGNAL ;
    PORT
      LAYER M4 ;
        RECT  23.676 26.928 23.76 26.952 ;
    END
  END o[265]
  PIN o[266]
    DIRECTION OUTPUT ;
    USE SIGNAL ;
    PORT
      LAYER M4 ;
        RECT  23.676 27.024 23.76 27.048 ;
    END
  END o[266]
  PIN o[267]
    DIRECTION OUTPUT ;
    USE SIGNAL ;
    PORT
      LAYER M4 ;
        RECT  23.676 27.12 23.76 27.144 ;
    END
  END o[267]
  PIN o[268]
    DIRECTION OUTPUT ;
    USE SIGNAL ;
    PORT
      LAYER M4 ;
        RECT  23.676 27.216 23.76 27.24 ;
    END
  END o[268]
  PIN o[269]
    DIRECTION OUTPUT ;
    USE SIGNAL ;
    PORT
      LAYER M4 ;
        RECT  23.676 27.312 23.76 27.336 ;
    END
  END o[269]
  PIN o[26]
    DIRECTION OUTPUT ;
    USE SIGNAL ;
    PORT
      LAYER M4 ;
        RECT  23.676 12.432 23.76 12.456 ;
    END
  END o[26]
  PIN o[270]
    DIRECTION OUTPUT ;
    USE SIGNAL ;
    PORT
      LAYER M4 ;
        RECT  23.676 27.408 23.76 27.432 ;
    END
  END o[270]
  PIN o[271]
    DIRECTION OUTPUT ;
    USE SIGNAL ;
    PORT
      LAYER M4 ;
        RECT  23.676 27.504 23.76 27.528 ;
    END
  END o[271]
  PIN o[272]
    DIRECTION OUTPUT ;
    USE SIGNAL ;
    PORT
      LAYER M4 ;
        RECT  23.676 27.6 23.76 27.624 ;
    END
  END o[272]
  PIN o[273]
    DIRECTION OUTPUT ;
    USE SIGNAL ;
    PORT
      LAYER M4 ;
        RECT  23.676 27.696 23.76 27.72 ;
    END
  END o[273]
  PIN o[274]
    DIRECTION OUTPUT ;
    USE SIGNAL ;
    PORT
      LAYER M4 ;
        RECT  23.676 27.792 23.76 27.816 ;
    END
  END o[274]
  PIN o[275]
    DIRECTION OUTPUT ;
    USE SIGNAL ;
    PORT
      LAYER M4 ;
        RECT  23.676 27.888 23.76 27.912 ;
    END
  END o[275]
  PIN o[27]
    DIRECTION OUTPUT ;
    USE SIGNAL ;
    PORT
      LAYER M4 ;
        RECT  23.676 12.528 23.76 12.552 ;
    END
  END o[27]
  PIN o[28]
    DIRECTION OUTPUT ;
    USE SIGNAL ;
    PORT
      LAYER M4 ;
        RECT  23.676 12.624 23.76 12.648 ;
    END
  END o[28]
  PIN o[29]
    DIRECTION OUTPUT ;
    USE SIGNAL ;
    PORT
      LAYER M4 ;
        RECT  23.676 12.72 23.76 12.744 ;
    END
  END o[29]
  PIN o[2]
    DIRECTION OUTPUT ;
    USE SIGNAL ;
    PORT
      LAYER M4 ;
        RECT  23.676 10.128 23.76 10.152 ;
    END
  END o[2]
  PIN o[30]
    DIRECTION OUTPUT ;
    USE SIGNAL ;
    PORT
      LAYER M4 ;
        RECT  23.676 12.816 23.76 12.84 ;
    END
  END o[30]
  PIN o[31]
    DIRECTION OUTPUT ;
    USE SIGNAL ;
    PORT
      LAYER M4 ;
        RECT  23.676 12.912 23.76 12.936 ;
    END
  END o[31]
  PIN o[32]
    DIRECTION OUTPUT ;
    USE SIGNAL ;
    PORT
      LAYER M4 ;
        RECT  23.676 13.008 23.76 13.032 ;
    END
  END o[32]
  PIN o[33]
    DIRECTION OUTPUT ;
    USE SIGNAL ;
    PORT
      LAYER M4 ;
        RECT  23.676 13.104 23.76 13.128 ;
    END
  END o[33]
  PIN o[34]
    DIRECTION OUTPUT ;
    USE SIGNAL ;
    PORT
      LAYER M4 ;
        RECT  23.676 13.2 23.76 13.224 ;
    END
  END o[34]
  PIN o[35]
    DIRECTION OUTPUT ;
    USE SIGNAL ;
    PORT
      LAYER M4 ;
        RECT  23.676 13.296 23.76 13.32 ;
    END
  END o[35]
  PIN o[36]
    DIRECTION OUTPUT ;
    USE SIGNAL ;
    PORT
      LAYER M4 ;
        RECT  23.676 13.392 23.76 13.416 ;
    END
  END o[36]
  PIN o[37]
    DIRECTION OUTPUT ;
    USE SIGNAL ;
    PORT
      LAYER M4 ;
        RECT  23.676 13.488 23.76 13.512 ;
    END
  END o[37]
  PIN o[38]
    DIRECTION OUTPUT ;
    USE SIGNAL ;
    PORT
      LAYER M4 ;
        RECT  23.676 13.584 23.76 13.608 ;
    END
  END o[38]
  PIN o[39]
    DIRECTION OUTPUT ;
    USE SIGNAL ;
    PORT
      LAYER M4 ;
        RECT  23.676 13.68 23.76 13.704 ;
    END
  END o[39]
  PIN o[3]
    DIRECTION OUTPUT ;
    USE SIGNAL ;
    PORT
      LAYER M4 ;
        RECT  23.676 10.224 23.76 10.248 ;
    END
  END o[3]
  PIN o[40]
    DIRECTION OUTPUT ;
    USE SIGNAL ;
    PORT
      LAYER M4 ;
        RECT  23.676 13.776 23.76 13.8 ;
    END
  END o[40]
  PIN o[41]
    DIRECTION OUTPUT ;
    USE SIGNAL ;
    PORT
      LAYER M4 ;
        RECT  23.676 13.872 23.76 13.896 ;
    END
  END o[41]
  PIN o[42]
    DIRECTION OUTPUT ;
    USE SIGNAL ;
    PORT
      LAYER M4 ;
        RECT  23.676 13.968 23.76 13.992 ;
    END
  END o[42]
  PIN o[43]
    DIRECTION OUTPUT ;
    USE SIGNAL ;
    PORT
      LAYER M4 ;
        RECT  23.676 14.064 23.76 14.088 ;
    END
  END o[43]
  PIN o[44]
    DIRECTION OUTPUT ;
    USE SIGNAL ;
    PORT
      LAYER M4 ;
        RECT  23.676 14.16 23.76 14.184 ;
    END
  END o[44]
  PIN o[45]
    DIRECTION OUTPUT ;
    USE SIGNAL ;
    PORT
      LAYER M4 ;
        RECT  23.676 14.256 23.76 14.28 ;
    END
  END o[45]
  PIN o[46]
    DIRECTION OUTPUT ;
    USE SIGNAL ;
    PORT
      LAYER M4 ;
        RECT  23.676 14.352 23.76 14.376 ;
    END
  END o[46]
  PIN o[47]
    DIRECTION OUTPUT ;
    USE SIGNAL ;
    PORT
      LAYER M4 ;
        RECT  23.676 14.448 23.76 14.472 ;
    END
  END o[47]
  PIN o[48]
    DIRECTION OUTPUT ;
    USE SIGNAL ;
    PORT
      LAYER M4 ;
        RECT  23.676 14.544 23.76 14.568 ;
    END
  END o[48]
  PIN o[49]
    DIRECTION OUTPUT ;
    USE SIGNAL ;
    PORT
      LAYER M4 ;
        RECT  23.676 14.64 23.76 14.664 ;
    END
  END o[49]
  PIN o[4]
    DIRECTION OUTPUT ;
    USE SIGNAL ;
    PORT
      LAYER M4 ;
        RECT  23.676 10.32 23.76 10.344 ;
    END
  END o[4]
  PIN o[50]
    DIRECTION OUTPUT ;
    USE SIGNAL ;
    PORT
      LAYER M4 ;
        RECT  23.676 14.736 23.76 14.76 ;
    END
  END o[50]
  PIN o[51]
    DIRECTION OUTPUT ;
    USE SIGNAL ;
    PORT
      LAYER M4 ;
        RECT  23.676 14.832 23.76 14.856 ;
    END
  END o[51]
  PIN o[52]
    DIRECTION OUTPUT ;
    USE SIGNAL ;
    PORT
      LAYER M4 ;
        RECT  23.676 14.928 23.76 14.952 ;
    END
  END o[52]
  PIN o[53]
    DIRECTION OUTPUT ;
    USE SIGNAL ;
    PORT
      LAYER M4 ;
        RECT  23.676 15.024 23.76 15.048 ;
    END
  END o[53]
  PIN o[54]
    DIRECTION OUTPUT ;
    USE SIGNAL ;
    PORT
      LAYER M4 ;
        RECT  23.676 15.12 23.76 15.144 ;
    END
  END o[54]
  PIN o[55]
    DIRECTION OUTPUT ;
    USE SIGNAL ;
    PORT
      LAYER M4 ;
        RECT  23.676 15.216 23.76 15.24 ;
    END
  END o[55]
  PIN o[56]
    DIRECTION OUTPUT ;
    USE SIGNAL ;
    PORT
      LAYER M4 ;
        RECT  23.676 15.312 23.76 15.336 ;
    END
  END o[56]
  PIN o[57]
    DIRECTION OUTPUT ;
    USE SIGNAL ;
    PORT
      LAYER M4 ;
        RECT  23.676 15.408 23.76 15.432 ;
    END
  END o[57]
  PIN o[58]
    DIRECTION OUTPUT ;
    USE SIGNAL ;
    PORT
      LAYER M4 ;
        RECT  23.676 15.504 23.76 15.528 ;
    END
  END o[58]
  PIN o[59]
    DIRECTION OUTPUT ;
    USE SIGNAL ;
    PORT
      LAYER M4 ;
        RECT  23.676 15.6 23.76 15.624 ;
    END
  END o[59]
  PIN o[5]
    DIRECTION OUTPUT ;
    USE SIGNAL ;
    PORT
      LAYER M4 ;
        RECT  23.676 10.416 23.76 10.44 ;
    END
  END o[5]
  PIN o[60]
    DIRECTION OUTPUT ;
    USE SIGNAL ;
    PORT
      LAYER M4 ;
        RECT  23.676 15.696 23.76 15.72 ;
    END
  END o[60]
  PIN o[61]
    DIRECTION OUTPUT ;
    USE SIGNAL ;
    PORT
      LAYER M4 ;
        RECT  23.676 15.792 23.76 15.816 ;
    END
  END o[61]
  PIN o[62]
    DIRECTION OUTPUT ;
    USE SIGNAL ;
    PORT
      LAYER M4 ;
        RECT  23.676 15.888 23.76 15.912 ;
    END
  END o[62]
  PIN o[63]
    DIRECTION OUTPUT ;
    USE SIGNAL ;
    PORT
      LAYER M4 ;
        RECT  23.676 15.984 23.76 16.008 ;
    END
  END o[63]
  PIN o[64]
    DIRECTION OUTPUT ;
    USE SIGNAL ;
    PORT
      LAYER M4 ;
        RECT  23.676 6.864 23.76 6.888 ;
    END
  END o[64]
  PIN o[65]
    DIRECTION OUTPUT ;
    USE SIGNAL ;
    PORT
      LAYER M4 ;
        RECT  23.676 6.96 23.76 6.984 ;
    END
  END o[65]
  PIN o[66]
    DIRECTION OUTPUT ;
    USE SIGNAL ;
    PORT
      LAYER M4 ;
        RECT  23.676 7.056 23.76 7.08 ;
    END
  END o[66]
  PIN o[67]
    DIRECTION OUTPUT ;
    USE SIGNAL ;
    PORT
      LAYER M4 ;
        RECT  23.676 7.152 23.76 7.176 ;
    END
  END o[67]
  PIN o[68]
    DIRECTION OUTPUT ;
    USE SIGNAL ;
    PORT
      LAYER M4 ;
        RECT  23.676 7.248 23.76 7.272 ;
    END
  END o[68]
  PIN o[69]
    DIRECTION OUTPUT ;
    USE SIGNAL ;
    PORT
      LAYER M4 ;
        RECT  23.676 7.344 23.76 7.368 ;
    END
  END o[69]
  PIN o[6]
    DIRECTION OUTPUT ;
    USE SIGNAL ;
    PORT
      LAYER M4 ;
        RECT  23.676 10.512 23.76 10.536 ;
    END
  END o[6]
  PIN o[70]
    DIRECTION OUTPUT ;
    USE SIGNAL ;
    PORT
      LAYER M4 ;
        RECT  23.676 7.44 23.76 7.464 ;
    END
  END o[70]
  PIN o[71]
    DIRECTION OUTPUT ;
    USE SIGNAL ;
    PORT
      LAYER M4 ;
        RECT  23.676 7.536 23.76 7.56 ;
    END
  END o[71]
  PIN o[72]
    DIRECTION OUTPUT ;
    USE SIGNAL ;
    PORT
      LAYER M4 ;
        RECT  23.676 7.632 23.76 7.656 ;
    END
  END o[72]
  PIN o[73]
    DIRECTION OUTPUT ;
    USE SIGNAL ;
    PORT
      LAYER M4 ;
        RECT  23.676 7.728 23.76 7.752 ;
    END
  END o[73]
  PIN o[74]
    DIRECTION OUTPUT ;
    USE SIGNAL ;
    PORT
      LAYER M4 ;
        RECT  23.676 7.824 23.76 7.848 ;
    END
  END o[74]
  PIN o[75]
    DIRECTION OUTPUT ;
    USE SIGNAL ;
    PORT
      LAYER M4 ;
        RECT  23.676 7.92 23.76 7.944 ;
    END
  END o[75]
  PIN o[76]
    DIRECTION OUTPUT ;
    USE SIGNAL ;
    PORT
      LAYER M4 ;
        RECT  23.676 8.016 23.76 8.04 ;
    END
  END o[76]
  PIN o[77]
    DIRECTION OUTPUT ;
    USE SIGNAL ;
    PORT
      LAYER M4 ;
        RECT  23.676 8.112 23.76 8.136 ;
    END
  END o[77]
  PIN o[78]
    DIRECTION OUTPUT ;
    USE SIGNAL ;
    PORT
      LAYER M4 ;
        RECT  23.676 8.208 23.76 8.232 ;
    END
  END o[78]
  PIN o[79]
    DIRECTION OUTPUT ;
    USE SIGNAL ;
    PORT
      LAYER M4 ;
        RECT  23.676 8.304 23.76 8.328 ;
    END
  END o[79]
  PIN o[7]
    DIRECTION OUTPUT ;
    USE SIGNAL ;
    PORT
      LAYER M4 ;
        RECT  23.676 10.608 23.76 10.632 ;
    END
  END o[7]
  PIN o[80]
    DIRECTION OUTPUT ;
    USE SIGNAL ;
    PORT
      LAYER M4 ;
        RECT  23.676 8.4 23.76 8.424 ;
    END
  END o[80]
  PIN o[81]
    DIRECTION OUTPUT ;
    USE SIGNAL ;
    PORT
      LAYER M4 ;
        RECT  23.676 8.496 23.76 8.52 ;
    END
  END o[81]
  PIN o[82]
    DIRECTION OUTPUT ;
    USE SIGNAL ;
    PORT
      LAYER M4 ;
        RECT  23.676 8.592 23.76 8.616 ;
    END
  END o[82]
  PIN o[83]
    DIRECTION OUTPUT ;
    USE SIGNAL ;
    PORT
      LAYER M4 ;
        RECT  23.676 8.688 23.76 8.712 ;
    END
  END o[83]
  PIN o[84]
    DIRECTION OUTPUT ;
    USE SIGNAL ;
    PORT
      LAYER M4 ;
        RECT  23.676 8.784 23.76 8.808 ;
    END
  END o[84]
  PIN o[85]
    DIRECTION OUTPUT ;
    USE SIGNAL ;
    PORT
      LAYER M4 ;
        RECT  23.676 8.88 23.76 8.904 ;
    END
  END o[85]
  PIN o[86]
    DIRECTION OUTPUT ;
    USE SIGNAL ;
    PORT
      LAYER M4 ;
        RECT  23.676 8.976 23.76 9 ;
    END
  END o[86]
  PIN o[87]
    DIRECTION OUTPUT ;
    USE SIGNAL ;
    PORT
      LAYER M4 ;
        RECT  23.676 9.072 23.76 9.096 ;
    END
  END o[87]
  PIN o[88]
    DIRECTION OUTPUT ;
    USE SIGNAL ;
    PORT
      LAYER M4 ;
        RECT  23.676 9.168 23.76 9.192 ;
    END
  END o[88]
  PIN o[89]
    DIRECTION OUTPUT ;
    USE SIGNAL ;
    PORT
      LAYER M4 ;
        RECT  23.676 9.264 23.76 9.288 ;
    END
  END o[89]
  PIN o[8]
    DIRECTION OUTPUT ;
    USE SIGNAL ;
    PORT
      LAYER M4 ;
        RECT  23.676 10.704 23.76 10.728 ;
    END
  END o[8]
  PIN o[90]
    DIRECTION OUTPUT ;
    USE SIGNAL ;
    PORT
      LAYER M4 ;
        RECT  23.676 9.36 23.76 9.384 ;
    END
  END o[90]
  PIN o[91]
    DIRECTION OUTPUT ;
    USE SIGNAL ;
    PORT
      LAYER M4 ;
        RECT  23.676 9.456 23.76 9.48 ;
    END
  END o[91]
  PIN o[92]
    DIRECTION OUTPUT ;
    USE SIGNAL ;
    PORT
      LAYER M4 ;
        RECT  23.676 9.552 23.76 9.576 ;
    END
  END o[92]
  PIN o[93]
    DIRECTION OUTPUT ;
    USE SIGNAL ;
    PORT
      LAYER M4 ;
        RECT  23.676 9.648 23.76 9.672 ;
    END
  END o[93]
  PIN o[94]
    DIRECTION OUTPUT ;
    USE SIGNAL ;
    PORT
      LAYER M4 ;
        RECT  23.676 9.744 23.76 9.768 ;
    END
  END o[94]
  PIN o[95]
    DIRECTION OUTPUT ;
    USE SIGNAL ;
    PORT
      LAYER M4 ;
        RECT  23.676 9.84 23.76 9.864 ;
    END
  END o[95]
  PIN o[96]
    DIRECTION OUTPUT ;
    USE SIGNAL ;
    PORT
      LAYER M4 ;
        RECT  23.676 3.792 23.76 3.816 ;
    END
  END o[96]
  PIN o[97]
    DIRECTION OUTPUT ;
    USE SIGNAL ;
    PORT
      LAYER M4 ;
        RECT  23.676 3.888 23.76 3.912 ;
    END
  END o[97]
  PIN o[98]
    DIRECTION OUTPUT ;
    USE SIGNAL ;
    PORT
      LAYER M4 ;
        RECT  23.676 3.984 23.76 4.008 ;
    END
  END o[98]
  PIN o[99]
    DIRECTION OUTPUT ;
    USE SIGNAL ;
    PORT
      LAYER M4 ;
        RECT  23.676 4.08 23.76 4.104 ;
    END
  END o[99]
  PIN o[9]
    DIRECTION OUTPUT ;
    USE SIGNAL ;
    PORT
      LAYER M4 ;
        RECT  23.676 10.8 23.76 10.824 ;
    END
  END o[9]
  PIN rs
    DIRECTION INPUT ;
    USE SIGNAL ;
    PORT
      LAYER M5 ;
        RECT  17.04 30.156 17.064 30.24 ;
    END
  END rs
  PIN VDD
    DIRECTION INOUT ;
    USE POWER ;
    PORT
      LAYER M5 ;
        RECT  18.792 2.151 18.912 28.089 ;
        RECT  13.392 2.151 13.512 28.089 ;
        RECT  7.992 2.151 8.112 28.089 ;
        RECT  2.592 2.151 2.712 28.089 ;
    END
  END VDD
  PIN VSS
    DIRECTION INOUT ;
    USE GROUND ;
    PORT
      LAYER M5 ;
        RECT  18.6 2.137 18.72 28.103 ;
        RECT  13.2 2.137 13.32 28.103 ;
        RECT  7.8 2.137 7.92 28.103 ;
        RECT  2.4 2.137 2.52 28.103 ;
    END
  END VSS
  # OT_OBS_CLOSED layer=M5 d_um=1.536 added=49
  OBS
    LAYER RVTN ;
     RECT  2.16 2.16 21.6 2.295 ;
     RECT  2.16 2.565 21.6 2.835 ;
     RECT  2.16 3.105 21.6 3.375 ;
     RECT  2.16 3.645 21.6 3.915 ;
     RECT  2.16 4.185 21.6 4.455 ;
     RECT  2.16 4.725 21.6 4.995 ;
     RECT  2.16 5.265 21.6 5.535 ;
     RECT  2.16 5.805 21.6 6.075 ;
     RECT  2.16 6.345 21.6 6.615 ;
     RECT  2.16 6.885 21.6 7.155 ;
     RECT  2.16 7.425 21.6 7.695 ;
     RECT  2.16 7.965 21.6 8.235 ;
     RECT  2.16 8.505 21.6 8.775 ;
     RECT  2.16 9.045 21.6 9.315 ;
     RECT  2.16 9.585 21.6 9.855 ;
     RECT  2.16 10.125 21.6 10.395 ;
     RECT  2.16 10.665 21.6 10.935 ;
     RECT  2.16 11.205 21.6 11.475 ;
     RECT  2.16 11.745 21.6 12.015 ;
     RECT  2.16 12.285 21.6 12.555 ;
     RECT  2.16 12.825 21.6 13.095 ;
     RECT  2.16 13.365 21.6 13.635 ;
     RECT  2.16 13.905 21.6 14.175 ;
     RECT  2.16 14.445 21.6 14.715 ;
     RECT  2.16 14.985 21.6 15.255 ;
     RECT  2.16 15.525 21.6 15.795 ;
     RECT  2.16 16.065 21.6 16.335 ;
     RECT  2.16 16.605 21.6 16.875 ;
     RECT  2.16 17.145 21.6 17.415 ;
     RECT  2.16 17.685 21.6 17.955 ;
     RECT  2.16 18.225 21.6 18.495 ;
     RECT  2.16 18.765 21.6 19.035 ;
     RECT  2.16 19.305 21.6 19.575 ;
     RECT  2.16 19.845 21.6 20.115 ;
     RECT  2.16 20.385 21.6 20.655 ;
     RECT  2.16 20.925 21.6 21.195 ;
     RECT  2.16 21.465 21.6 21.735 ;
     RECT  2.16 22.005 21.6 22.275 ;
     RECT  2.16 22.545 21.6 22.815 ;
     RECT  2.16 23.085 21.6 23.355 ;
     RECT  2.16 23.625 21.6 23.895 ;
     RECT  2.16 24.165 21.6 24.435 ;
     RECT  2.16 24.705 21.6 24.975 ;
     RECT  2.16 25.245 21.6 25.515 ;
     RECT  2.16 25.785 21.6 26.055 ;
     RECT  2.16 26.325 21.6 26.595 ;
     RECT  2.16 26.865 21.6 27.135 ;
     RECT  2.16 27.405 21.6 27.675 ;
     RECT  2.16 27.945 21.6 28.08 ;
    LAYER RVTP ;
     RECT  2.16 2.295 21.6 2.565 ;
     RECT  2.16 2.835 21.6 3.105 ;
     RECT  2.16 3.375 21.6 3.645 ;
     RECT  2.16 3.915 21.6 4.185 ;
     RECT  2.16 4.455 21.6 4.725 ;
     RECT  2.16 4.995 21.6 5.265 ;
     RECT  2.16 5.535 21.6 5.805 ;
     RECT  2.16 6.075 21.6 6.345 ;
     RECT  2.16 6.615 21.6 6.885 ;
     RECT  2.16 7.155 21.6 7.425 ;
     RECT  2.16 7.695 21.6 7.965 ;
     RECT  2.16 8.235 21.6 8.505 ;
     RECT  2.16 8.775 21.6 9.045 ;
     RECT  2.16 9.315 21.6 9.585 ;
     RECT  2.16 9.855 21.6 10.125 ;
     RECT  2.16 10.395 21.6 10.665 ;
     RECT  2.16 10.935 21.6 11.205 ;
     RECT  2.16 11.475 21.6 11.745 ;
     RECT  2.16 12.015 21.6 12.285 ;
     RECT  2.16 12.555 21.6 12.825 ;
     RECT  2.16 13.095 21.6 13.365 ;
     RECT  2.16 13.635 21.6 13.905 ;
     RECT  2.16 14.175 21.6 14.445 ;
     RECT  2.16 14.715 21.6 14.985 ;
     RECT  2.16 15.255 21.6 15.525 ;
     RECT  2.16 15.795 21.6 16.065 ;
     RECT  2.16 16.335 21.6 16.605 ;
     RECT  2.16 16.875 21.6 17.145 ;
     RECT  2.16 17.415 21.6 17.685 ;
     RECT  2.16 17.955 21.6 18.225 ;
     RECT  2.16 18.495 21.6 18.765 ;
     RECT  2.16 19.035 21.6 19.305 ;
     RECT  2.16 19.575 21.6 19.845 ;
     RECT  2.16 20.115 21.6 20.385 ;
     RECT  2.16 20.655 21.6 20.925 ;
     RECT  2.16 21.195 21.6 21.465 ;
     RECT  2.16 21.735 21.6 22.005 ;
     RECT  2.16 22.275 21.6 22.545 ;
     RECT  2.16 22.815 21.6 23.085 ;
     RECT  2.16 23.355 21.6 23.625 ;
     RECT  2.16 23.895 21.6 24.165 ;
     RECT  2.16 24.435 21.6 24.705 ;
     RECT  2.16 24.975 21.6 25.245 ;
     RECT  2.16 25.515 21.6 25.785 ;
     RECT  2.16 26.055 21.6 26.325 ;
     RECT  2.16 26.595 21.6 26.865 ;
     RECT  2.16 27.135 21.6 27.405 ;
     RECT  2.16 27.675 21.6 27.945 ;
    LAYER M1 ;
     RECT  2.16 2.151 21.6 28.089 ;
    LAYER M2 ;
     RECT  0.031 19.161 0.067 19.179 ;
     RECT  0.031 11.286 0.103 11.304 ;
     RECT  0.067 14.652 0.103 14.67 ;
     RECT  0.067 18.936 0.103 19.179 ;
     RECT  0.031 22.176 0.103 22.194 ;
     RECT  0.031 27.576 0.103 27.594 ;
     RECT  0.103 26.604 0.131 27.594 ;
     RECT  0.103 4.77 0.139 4.788 ;
     RECT  0.103 14.184 0.139 16.128 ;
     RECT  0.103 18.936 0.139 19.908 ;
     RECT  0.103 20.97 0.139 20.988 ;
     RECT  0.103 21.78 0.139 22.194 ;
     RECT  0.139 18.936 0.167 22.23 ;
     RECT  0.103 23.832 0.175 24.39 ;
     RECT  0.131 26.604 0.175 27.279 ;
     RECT  0.175 26.37 0.203 27.279 ;
     RECT  0.139 14.184 0.211 16.866 ;
     RECT  0.139 17.622 0.211 17.64 ;
     RECT  0.139 2.538 0.239 2.556 ;
     RECT  0.103 8.856 0.239 9.27 ;
     RECT  0.211 14.184 0.239 17.64 ;
     RECT  0.103 7.938 0.247 7.956 ;
     RECT  0.175 23.328 0.499 24.39 ;
     RECT  0.103 25.218 0.499 25.236 ;
     RECT  0.103 10.638 0.535 11.304 ;
     RECT  0.167 19.35 0.535 22.23 ;
     RECT  0.499 23.328 0.535 25.236 ;
     RECT  0.535 19.35 1.147 25.236 ;
     RECT  0.203 26.37 1.147 26.856 ;
     RECT  0.239 14.184 1.363 15.246 ;
     RECT  0.535 10.638 1.399 11.844 ;
     RECT  1.363 14.184 1.543 15.318 ;
     RECT  1.543 13.95 1.579 15.318 ;
     RECT  1.147 26.37 1.687 27.36 ;
     RECT  0.239 16.11 1.723 17.64 ;
     RECT  1.147 18.702 1.723 25.236 ;
     RECT  1.579 13.41 1.939 15.318 ;
     RECT  0.239 9.252 1.975 9.27 ;
     RECT  1.399 10.17 2.119 11.844 ;
     RECT  1.939 13.032 2.119 15.318 ;
     RECT  0.535 3.96 2.16 3.978 ;
     RECT  0.139 4.77 2.16 5.49 ;
     RECT  0.103 6.696 2.16 6.714 ;
     RECT  0.247 7.938 2.16 8.298 ;
     RECT  1.975 9.252 2.16 9.378 ;
     RECT  2.119 10.17 2.16 15.318 ;
     RECT  1.723 16.11 2.16 25.236 ;
     RECT  1.687 26.37 2.16 27.504 ;
     RECT  2.16 2.151 14.251 28.089 ;
     RECT  14.251 2.106 15.655 28.089 ;
     RECT  15.655 2.034 16.519 28.089 ;
     RECT  16.519 1.764 20.399 28.089 ;
     RECT  20.399 2.034 20.831 28.089 ;
     RECT  20.831 2.151 21.6 28.089 ;
     RECT  21.6 2.196 22.667 27.864 ;
     RECT  22.667 2.304 22.703 27.864 ;
     RECT  22.703 2.376 22.775 27.864 ;
     RECT  22.775 2.646 22.811 13.194 ;
     RECT  22.775 14.076 22.811 25.884 ;
     RECT  22.775 26.766 22.811 27.864 ;
     RECT  22.811 6.588 22.847 7.65 ;
     RECT  22.811 8.514 22.847 9.27 ;
     RECT  22.811 12.906 22.847 13.194 ;
     RECT  22.811 20.196 22.847 22.572 ;
     RECT  22.811 23.706 22.847 25.884 ;
     RECT  22.847 12.906 22.883 13.086 ;
     RECT  22.811 14.886 22.883 19.332 ;
     RECT  22.847 25.866 22.883 25.884 ;
     RECT  22.811 27.306 22.883 27.324 ;
     RECT  22.847 23.904 22.955 25.074 ;
     RECT  22.811 3.276 23.495 5.832 ;
     RECT  22.847 6.588 23.567 7.38 ;
     RECT  22.847 8.514 23.575 8.802 ;
     RECT  23.495 3.276 23.639 5.454 ;
     RECT  23.567 6.696 23.639 7.38 ;
     RECT  23.575 8.514 23.639 9.072 ;
     RECT  22.811 10.206 23.639 11.772 ;
     RECT  22.883 14.886 23.639 18.792 ;
     RECT  22.955 24.786 23.639 25.074 ;
     RECT  23.639 3.996 23.675 5.454 ;
     RECT  23.639 6.786 23.675 7.38 ;
     RECT  23.639 8.676 23.675 9.072 ;
     RECT  23.639 10.206 23.675 10.854 ;
     RECT  23.639 11.754 23.675 11.772 ;
     RECT  22.883 12.906 23.675 12.924 ;
     RECT  23.639 14.886 23.675 16.974 ;
     RECT  23.639 17.73 23.675 18.792 ;
     RECT  22.847 21.276 23.675 22.572 ;
     RECT  22.955 23.904 23.675 23.922 ;
     RECT  23.639 24.786 23.675 24.804 ;
     RECT  23.675 4.581 23.711 4.752 ;
     RECT  23.675 6.894 23.711 6.912 ;
     RECT  23.647 0.756 23.747 0.774 ;
     RECT  23.711 4.734 23.747 4.752 ;
     RECT  23.647 14.076 23.747 14.094 ;
     RECT  23.675 16.956 23.747 16.974 ;
    LAYER M3 ;
     RECT  23.652 0.715 23.67 0.751 ;
     RECT  22.248 0.811 22.266 1.003 ;
     RECT  22.248 1.003 22.806 1.195 ;
     RECT  22.212 1.195 22.806 1.387 ;
     RECT  21.132 1.291 21.15 1.675 ;
     RECT  22.212 1.387 22.842 1.675 ;
     RECT  20.34 1.579 20.358 1.759 ;
     RECT  20.34 1.759 20.394 1.771 ;
     RECT  21.132 1.675 22.842 1.771 ;
     RECT  20.34 1.771 22.842 1.831 ;
     RECT  16.524 1.759 16.542 1.876 ;
     RECT  18.324 1.831 18.342 1.876 ;
     RECT  16.524 1.876 17.118 1.921 ;
     RECT  18.324 1.876 18.414 1.921 ;
     RECT  18.324 1.921 18.486 1.957 ;
     RECT  20.232 1.831 22.842 1.957 ;
     RECT  20.016 1.957 22.842 1.963 ;
     RECT  15.66 2.029 15.678 2.065 ;
     RECT  16.524 1.921 17.226 2.065 ;
     RECT  17.964 1.957 18.486 2.065 ;
     RECT  19.368 1.963 22.842 2.065 ;
     RECT  15.66 2.065 17.226 2.191 ;
     RECT  17.964 2.065 22.842 2.191 ;
     RECT  15.66 2.191 22.842 2.263 ;
     RECT  6.012 2.227 6.03 2.299 ;
     RECT  7.815 2.143 7.905 2.299 ;
     RECT  5.22 2.299 5.238 2.347 ;
     RECT  6.012 2.299 6.354 2.347 ;
     RECT  7.815 2.299 8.514 2.347 ;
     RECT  13.215 2.143 13.305 2.347 ;
     RECT  14.256 2.101 14.274 2.347 ;
     RECT  15.408 2.263 22.842 2.347 ;
     RECT  23.652 0.751 23.742 2.347 ;
     RECT  6.012 2.347 6.858 2.371 ;
     RECT  11.628 2.335 11.646 2.371 ;
     RECT  13.215 2.347 14.274 2.371 ;
     RECT  15.084 2.347 22.842 2.371 ;
     RECT  2.415 2.143 2.505 2.413 ;
     RECT  10.872 2.371 11.646 2.443 ;
     RECT  12.384 2.335 12.402 2.443 ;
     RECT  13.215 2.371 22.842 2.443 ;
     RECT  23.616 2.347 23.742 2.443 ;
     RECT  6.012 2.371 6.93 2.461 ;
     RECT  7.815 2.347 8.55 2.461 ;
     RECT  10.872 2.443 12.474 2.461 ;
     RECT  0.144 2.299 0.162 2.491 ;
     RECT  5.148 2.347 5.238 2.491 ;
     RECT  10.188 2.461 12.474 2.533 ;
     RECT  13.215 2.443 23.742 2.533 ;
     RECT  3.42 2.251 3.438 2.539 ;
     RECT  0.144 2.491 0.234 2.561 ;
     RECT  2.415 2.413 2.697 2.632 ;
     RECT  5.148 2.491 5.274 2.635 ;
     RECT  6.012 2.461 8.55 2.635 ;
     RECT  5.148 2.635 8.55 2.641 ;
     RECT  3.42 2.539 3.978 2.803 ;
     RECT  5.148 2.641 9.414 2.803 ;
     RECT  2.304 2.632 2.697 2.827 ;
     RECT  3.42 2.803 9.414 2.827 ;
     RECT  2.304 2.827 9.414 2.839 ;
     RECT  10.188 2.533 23.742 2.839 ;
     RECT  2.304 2.839 23.742 3.677 ;
     RECT  0.144 2.561 0.162 3.787 ;
     RECT  0.144 3.787 0.342 3.955 ;
     RECT  1.152 3.739 1.17 3.955 ;
     RECT  2.304 3.677 8.19 4.117 ;
     RECT  0.144 3.955 1.17 4.157 ;
     RECT  2.232 4.117 8.19 4.559 ;
     RECT  0.144 4.157 0.558 4.589 ;
     RECT  2.304 4.559 8.19 4.651 ;
     RECT  8.928 3.677 23.742 4.651 ;
     RECT  2.304 4.651 23.742 4.757 ;
     RECT  0.144 4.589 0.198 4.765 ;
     RECT  1.152 5.323 1.17 5.501 ;
     RECT  0.108 4.765 0.198 5.515 ;
     RECT  0.108 5.515 0.342 5.549 ;
     RECT  0.144 5.549 0.342 5.645 ;
     RECT  0.144 5.645 0.198 5.741 ;
     RECT  2.304 4.757 23.706 5.837 ;
     RECT  0.18 5.741 0.198 6.221 ;
     RECT  2.304 5.837 22.806 6.475 ;
     RECT  23.58 5.837 23.706 6.571 ;
     RECT  23.544 6.571 23.706 6.611 ;
     RECT  0.108 6.691 0.126 6.893 ;
     RECT  23.58 6.611 23.706 6.917 ;
     RECT  0.216 7.051 0.342 7.181 ;
     RECT  23.58 6.917 23.67 7.259 ;
     RECT  0.216 7.181 0.306 7.421 ;
     RECT  2.268 6.475 22.806 7.565 ;
     RECT  22.752 7.565 22.806 7.627 ;
     RECT  23.652 7.259 23.67 8.107 ;
     RECT  0.108 7.933 0.126 8.275 ;
     RECT  2.268 7.565 21.978 8.299 ;
     RECT  22.752 7.627 22.842 8.299 ;
     RECT  2.268 8.299 22.842 8.621 ;
     RECT  0.108 8.275 0.27 8.875 ;
     RECT  0.108 8.875 0.342 9.005 ;
     RECT  23.616 8.107 23.67 9.019 ;
     RECT  23.58 9.019 23.67 9.077 ;
     RECT  2.304 8.621 22.842 9.355 ;
     RECT  0.108 9.005 0.27 9.389 ;
     RECT  1.98 9.355 22.842 9.485 ;
     RECT  22.176 9.485 22.842 9.869 ;
     RECT  0.108 9.389 0.162 10.109 ;
     RECT  1.98 9.485 21.294 10.165 ;
     RECT  1.404 10.165 21.294 10.267 ;
     RECT  1.404 10.267 21.33 10.435 ;
     RECT  22.176 9.869 22.806 10.435 ;
     RECT  1.404 10.435 22.806 10.669 ;
     RECT  1.404 10.669 22.878 10.705 ;
     RECT  0.864 10.705 22.878 10.733 ;
     RECT  0.108 10.109 0.126 11.101 ;
     RECT  0.864 10.733 21.114 11.101 ;
     RECT  0.108 11.101 21.114 11.281 ;
     RECT  0.036 11.281 21.114 11.479 ;
     RECT  0.036 11.479 21.186 11.515 ;
     RECT  22.176 10.733 22.878 11.515 ;
     RECT  23.652 9.077 23.67 11.551 ;
     RECT  0.036 11.515 22.878 11.659 ;
     RECT  23.616 11.551 23.67 11.659 ;
     RECT  0.036 11.659 23.67 11.777 ;
     RECT  0.036 11.777 23.634 11.885 ;
     RECT  0.036 11.885 21.474 11.939 ;
     RECT  22.212 11.885 23.634 11.981 ;
     RECT  0.036 11.939 21.33 12.653 ;
     RECT  23.652 12.523 23.67 12.929 ;
     RECT  22.212 11.981 22.806 13.003 ;
     RECT  22.176 13.003 22.806 13.063 ;
     RECT  22.176 13.063 22.878 13.387 ;
     RECT  0.036 12.653 21.294 13.703 ;
     RECT  22.14 13.387 22.878 13.805 ;
     RECT  22.14 13.805 22.806 13.937 ;
     RECT  22.212 13.937 22.806 14.009 ;
     RECT  23.652 14.059 23.67 14.071 ;
     RECT  0.036 13.703 21.258 14.135 ;
     RECT  22.248 14.009 22.806 15.115 ;
     RECT  0.036 14.135 21.114 15.295 ;
     RECT  21.888 15.115 22.806 15.295 ;
     RECT  0.036 15.295 22.806 15.331 ;
     RECT  0.036 15.331 22.842 16.403 ;
     RECT  22.212 16.403 22.842 16.589 ;
     RECT  23.652 14.071 23.742 16.747 ;
     RECT  0.036 16.403 21.474 16.877 ;
     RECT  23.616 16.747 23.742 16.979 ;
     RECT  23.616 16.979 23.67 17.131 ;
     RECT  22.212 16.589 22.806 17.419 ;
     RECT  23.58 17.131 23.67 17.519 ;
     RECT  23.616 17.519 23.67 17.609 ;
     RECT  0.036 16.877 21.294 17.851 ;
     RECT  22.176 17.419 22.806 17.995 ;
     RECT  0.036 17.851 21.402 18.187 ;
     RECT  22.176 17.995 22.878 18.187 ;
     RECT  0.036 18.187 22.878 18.413 ;
     RECT  1.152 18.413 22.878 18.599 ;
     RECT  1.152 18.599 21.294 18.725 ;
     RECT  23.652 17.609 23.67 18.797 ;
     RECT  22.14 18.599 22.878 19.139 ;
     RECT  0.036 18.413 0.414 19.184 ;
     RECT  1.368 18.725 21.294 19.277 ;
     RECT  22.392 19.139 22.878 19.337 ;
     RECT  2.415 19.277 21.294 19.345 ;
     RECT  1.368 19.277 1.674 19.373 ;
     RECT  1.44 19.373 1.674 19.661 ;
     RECT  22.392 19.337 22.806 19.915 ;
     RECT  2.415 19.345 21.366 20.011 ;
     RECT  22.248 19.915 22.806 20.011 ;
     RECT  0.108 19.184 0.414 20.141 ;
     RECT  2.304 20.011 22.806 20.191 ;
     RECT  0.144 20.141 0.414 20.425 ;
     RECT  0.144 20.425 0.558 20.965 ;
     RECT  2.304 20.191 22.842 21.361 ;
     RECT  2.304 21.361 22.878 22.075 ;
     RECT  23.652 21.259 23.67 22.075 ;
     RECT  2.304 22.075 23.67 22.154 ;
     RECT  2.304 22.154 22.914 22.156 ;
     RECT  0.108 20.965 0.558 22.171 ;
     RECT  23.652 22.154 23.67 22.577 ;
     RECT  2.268 22.156 22.914 22.847 ;
     RECT  2.304 22.847 22.914 23.021 ;
     RECT  2.304 23.021 22.842 23.117 ;
     RECT  0.036 22.171 0.558 23.501 ;
     RECT  0.036 23.501 0.198 23.597 ;
     RECT  2.304 23.117 21.726 23.927 ;
     RECT  5.688 23.927 21.726 23.947 ;
     RECT  5.688 23.947 21.87 23.971 ;
     RECT  22.716 23.117 22.842 23.971 ;
     RECT  2.304 23.927 4.842 24.089 ;
     RECT  5.688 23.971 22.842 24.097 ;
     RECT  23.652 23.563 23.67 24.097 ;
     RECT  2.304 24.089 4.662 24.205 ;
     RECT  1.44 19.661 1.458 24.269 ;
     RECT  0.036 23.597 0.126 24.439 ;
     RECT  5.688 24.097 23.67 24.781 ;
     RECT  5.544 24.781 23.67 24.809 ;
     RECT  2.268 24.205 4.662 24.845 ;
     RECT  5.544 24.809 23.634 25.079 ;
     RECT  0.036 24.439 0.558 25.133 ;
     RECT  5.544 25.079 22.95 25.133 ;
     RECT  2.304 24.845 4.662 25.177 ;
     RECT  5.544 25.133 22.842 25.177 ;
     RECT  0.036 25.133 0.522 25.229 ;
     RECT  2.304 25.177 22.842 25.852 ;
     RECT  2.268 25.852 22.842 25.861 ;
     RECT  2.268 25.861 22.878 25.987 ;
     RECT  0.036 25.229 0.126 26.011 ;
     RECT  2.196 25.987 22.878 26.093 ;
     RECT  2.304 26.093 22.878 26.321 ;
     RECT  5.724 26.321 22.878 26.357 ;
     RECT  0.036 26.011 0.162 26.365 ;
     RECT  0.036 26.365 0.198 26.833 ;
     RECT  0.036 26.833 0.558 27.175 ;
     RECT  1.404 25.015 1.422 27.175 ;
     RECT  2.304 26.321 4.95 27.175 ;
     RECT  5.796 26.357 22.878 27.175 ;
     RECT  2.304 27.175 22.878 27.203 ;
     RECT  10.548 27.203 22.878 27.329 ;
     RECT  10.548 27.329 14.958 27.389 ;
     RECT  15.804 27.329 22.878 27.389 ;
     RECT  2.304 27.203 9.81 27.401 ;
     RECT  2.304 27.401 9.702 27.473 ;
     RECT  0.036 27.175 1.422 27.481 ;
     RECT  2.304 27.473 8.154 27.481 ;
     RECT  12.168 27.389 14.958 27.509 ;
     RECT  0.036 27.481 8.154 27.599 ;
     RECT  9.288 27.473 9.702 27.599 ;
     RECT  10.548 27.389 10.962 27.599 ;
     RECT  12.168 27.509 14.238 27.599 ;
     RECT  15.984 27.389 22.878 27.629 ;
     RECT  9.684 27.599 9.702 27.635 ;
     RECT  12.276 27.599 14.238 27.671 ;
     RECT  0.108 27.599 8.154 27.707 ;
     RECT  5.796 27.707 8.154 27.743 ;
     RECT  12.492 27.671 14.238 27.743 ;
     RECT  5.796 27.743 5.922 27.779 ;
     RECT  22.14 27.629 22.878 27.779 ;
     RECT  22.752 27.779 22.878 27.821 ;
     RECT  0.108 27.707 5.022 27.869 ;
     RECT  5.796 27.779 5.85 27.869 ;
     RECT  15.984 27.629 21.258 27.869 ;
     RECT  22.788 27.821 22.878 27.869 ;
     RECT  4.284 27.869 5.022 27.905 ;
     RECT  5.796 27.869 5.814 27.905 ;
     RECT  6.84 27.743 8.154 27.905 ;
     RECT  10.908 27.599 10.962 27.905 ;
     RECT  13.215 27.743 14.238 27.905 ;
     RECT  16.164 27.869 16.866 27.905 ;
     RECT  17.604 27.869 17.73 27.905 ;
     RECT  19.8 27.869 20.25 27.905 ;
     RECT  21.24 27.869 21.258 27.905 ;
     RECT  22.86 27.869 22.878 27.917 ;
     RECT  4.356 27.905 5.022 27.941 ;
     RECT  10.944 27.905 10.962 27.941 ;
     RECT  13.215 27.905 13.662 27.941 ;
     RECT  16.74 27.905 16.758 27.941 ;
     RECT  17.604 27.905 17.622 27.941 ;
     RECT  18.576 27.869 18.954 27.941 ;
     RECT  0.108 27.869 3.402 28.013 ;
     RECT  19.8 27.905 19.818 28.049 ;
     RECT  6.84 27.905 7.905 28.097 ;
     RECT  13.215 27.941 13.305 28.097 ;
     RECT  18.615 27.941 18.705 28.097 ;
     RECT  0.108 28.013 3.366 28.109 ;
     RECT  1.152 28.109 3.366 28.205 ;
     RECT  6.84 28.097 7.398 28.301 ;
     RECT  7.38 28.301 7.398 28.397 ;
     RECT  1.152 28.205 2.826 28.685 ;
     RECT  1.152 28.685 2.754 28.781 ;
     RECT  1.152 28.781 2.394 28.877 ;
     RECT  0.108 28.109 0.126 28.973 ;
     RECT  1.152 28.877 1.71 29.165 ;
     RECT  1.188 29.165 1.71 29.357 ;
     RECT  1.188 29.357 1.206 29.453 ;
    LAYER M4 ;
     RECT  0.06 2.256 1.217 29.448 ;
     RECT  1.217 2.256 1.721 29.352 ;
     RECT  1.721 2.256 2.405 28.872 ;
     RECT  2.405 2.256 2.408 28.776 ;
     RECT  2.408 2.148 2.512 28.776 ;
     RECT  2.512 2.256 2.704 28.776 ;
     RECT  2.704 20.208 2.765 28.776 ;
     RECT  2.704 2.256 2.837 18.84 ;
     RECT  2.765 20.208 2.837 28.68 ;
     RECT  2.837 2.256 3.449 16.008 ;
     RECT  2.837 20.208 3.665 28.392 ;
     RECT  3.449 2.304 3.98 16.008 ;
     RECT  2.837 17.184 3.98 18.84 ;
     RECT  3.98 2.304 3.989 18.84 ;
     RECT  3.665 22.08 4.012 28.392 ;
     RECT  3.989 15.024 4.025 18.84 ;
     RECT  4.012 24.72 4.025 28.392 ;
     RECT  3.989 2.304 4.211 13.992 ;
     RECT  4.025 16.512 4.213 18.84 ;
     RECT  3.665 20.208 4.213 20.376 ;
     RECT  4.213 16.512 4.277 20.376 ;
     RECT  4.012 22.08 4.421 23.688 ;
     RECT  4.211 2.304 4.817 13.896 ;
     RECT  4.817 2.304 4.835 10.584 ;
     RECT  4.277 18.672 4.853 20.376 ;
     RECT  4.421 22.08 5.033 23.4 ;
     RECT  5.033 22.08 5.093 22.296 ;
     RECT  5.093 21.648 5.171 22.296 ;
     RECT  4.025 15.024 5.209 15.384 ;
     RECT  4.277 16.512 5.209 17.352 ;
     RECT  4.835 2.304 5.249 10.344 ;
     RECT  5.033 23.376 5.249 23.4 ;
     RECT  5.249 2.496 5.285 10.344 ;
     RECT  4.025 25.152 5.573 28.392 ;
     RECT  4.853 19.488 5.825 20.376 ;
     RECT  5.209 15.024 5.893 17.352 ;
     RECT  5.171 21.648 5.933 21.672 ;
     RECT  5.893 14.976 6.109 17.64 ;
     RECT  4.817 11.712 6.181 13.896 ;
     RECT  6.109 14.976 6.181 18.36 ;
     RECT  5.825 19.488 6.181 20.232 ;
     RECT  6.181 11.376 6.277 13.896 ;
     RECT  6.181 14.976 6.277 20.232 ;
     RECT  5.857 24.528 6.284 24.552 ;
     RECT  6.277 11.376 6.323 20.232 ;
     RECT  6.284 24.432 6.329 24.552 ;
     RECT  6.329 24.432 6.371 24.456 ;
     RECT  5.573 26.016 6.371 28.392 ;
     RECT  6.325 21.792 6.397 21.912 ;
     RECT  6.397 21.792 6.517 22.2 ;
     RECT  6.325 23.328 6.517 23.352 ;
     RECT  5.285 2.544 6.541 10.344 ;
     RECT  6.323 11.376 6.541 13.464 ;
     RECT  6.541 2.544 6.653 13.464 ;
     RECT  6.653 2.544 6.829 7.128 ;
     RECT  6.653 8.16 6.833 13.464 ;
     RECT  6.323 14.64 7.333 20.232 ;
     RECT  6.371 26.112 7.333 28.392 ;
     RECT  7.333 25.44 7.409 28.392 ;
     RECT  6.829 2.352 7.808 7.128 ;
     RECT  6.833 8.16 7.808 10.248 ;
     RECT  6.833 11.424 7.808 13.368 ;
     RECT  7.333 14.64 7.808 20.712 ;
     RECT  6.517 21.792 7.808 23.352 ;
     RECT  7.409 25.44 7.808 28.092 ;
     RECT  7.808 2.148 7.912 28.092 ;
     RECT  7.912 2.352 8.104 27.822 ;
     RECT  8.104 27.408 8.165 27.432 ;
     RECT  8.104 11.424 8.201 13.368 ;
     RECT  8.104 2.352 8.561 6.12 ;
     RECT  8.104 7.104 8.633 10.44 ;
     RECT  8.104 23.952 8.885 26.328 ;
     RECT  8.885 24.912 9.109 26.328 ;
     RECT  9.109 24.912 9.155 26.568 ;
     RECT  9.089 23.904 9.173 23.928 ;
     RECT  8.633 8.16 9.277 10.44 ;
     RECT  8.104 14.976 9.277 22.248 ;
     RECT  9.277 14.976 9.313 22.776 ;
     RECT  9.155 25.44 9.349 26.568 ;
     RECT  9.313 14.88 9.421 22.776 ;
     RECT  9.277 8.16 9.529 10.728 ;
     RECT  8.201 11.712 9.529 13.368 ;
     RECT  9.421 14.448 9.529 22.776 ;
     RECT  9.529 14.352 9.533 22.776 ;
     RECT  9.529 8.16 9.637 13.368 ;
     RECT  9.533 14.352 9.637 21.96 ;
     RECT  9.637 8.16 9.683 21.96 ;
     RECT  9.349 25.44 9.781 26.712 ;
     RECT  9.683 8.16 9.893 18.6 ;
     RECT  8.633 7.104 9.961 7.176 ;
     RECT  9.893 8.16 9.961 17.976 ;
     RECT  9.781 25.44 10.037 26.904 ;
     RECT  8.561 2.544 10.249 6.12 ;
     RECT  9.961 7.104 10.249 17.976 ;
     RECT  10.037 25.44 10.309 26.808 ;
     RECT  10.309 24.384 10.396 26.808 ;
     RECT  10.249 2.544 10.541 17.976 ;
     RECT  9.683 19.776 10.613 21.96 ;
     RECT  10.541 2.544 10.825 13.368 ;
     RECT  9.817 23.088 10.825 23.352 ;
     RECT  10.825 2.496 10.861 13.368 ;
     RECT  10.541 14.448 10.969 17.976 ;
     RECT  10.396 24.672 11.045 26.808 ;
     RECT  10.861 2.4 11.081 13.368 ;
     RECT  10.969 14.448 11.081 18.264 ;
     RECT  10.613 20.064 11.081 21.96 ;
     RECT  11.081 2.448 11.297 13.368 ;
     RECT  11.081 20.4 11.375 21.96 ;
     RECT  10.825 23.088 11.375 23.448 ;
     RECT  11.045 26.544 11.653 26.808 ;
     RECT  11.045 24.672 11.725 25.56 ;
     RECT  11.297 8.448 12.157 13.368 ;
     RECT  11.081 14.736 12.157 18.264 ;
     RECT  11.653 26.544 12.157 27.384 ;
     RECT  11.375 20.4 12.229 23.448 ;
     RECT  11.725 24.624 12.229 25.56 ;
     RECT  11.297 2.448 12.373 7.368 ;
     RECT  12.157 8.448 12.373 18.264 ;
     RECT  12.157 26.544 12.481 27.576 ;
     RECT  12.373 2.448 12.949 18.264 ;
     RECT  12.949 2.448 13.093 18.456 ;
     RECT  13.093 2.448 13.208 18.552 ;
     RECT  12.229 20.4 13.208 25.56 ;
     RECT  12.481 26.544 13.208 27.72 ;
     RECT  13.208 2.148 13.312 28.092 ;
     RECT  13.312 2.352 13.504 27.822 ;
     RECT  13.504 20.688 13.565 21.288 ;
     RECT  13.565 20.976 13.601 21.288 ;
     RECT  13.504 22.464 13.619 26.568 ;
     RECT  13.619 22.464 13.673 25.752 ;
     RECT  13.673 25.728 14.105 25.752 ;
     RECT  13.673 22.464 14.357 24.696 ;
     RECT  13.601 21.072 14.677 21.288 ;
     RECT  14.677 27.168 14.713 27.192 ;
     RECT  14.677 21.072 14.924 21.384 ;
     RECT  14.357 22.464 14.924 24.504 ;
     RECT  13.504 2.352 15.113 19.608 ;
     RECT  15.113 3.312 15.145 19.608 ;
     RECT  14.924 21.072 15.145 24.504 ;
     RECT  15.145 3.312 15.361 24.504 ;
     RECT  14.713 26.592 15.433 27.384 ;
     RECT  15.361 3.312 15.541 25.32 ;
     RECT  15.433 26.448 15.541 27.384 ;
     RECT  15.541 3.312 15.797 27.384 ;
     RECT  15.797 3.312 15.833 6.696 ;
     RECT  15.797 7.92 15.833 27.384 ;
     RECT  15.833 24.384 16.301 27.336 ;
     RECT  15.833 3.312 16.585 6.6 ;
     RECT  16.585 2.736 16.697 6.6 ;
     RECT  16.697 2.832 16.733 6.6 ;
     RECT  15.833 7.92 16.985 23.112 ;
     RECT  16.301 26.112 17.075 27.336 ;
     RECT  16.985 7.92 17.129 21.144 ;
     RECT  16.985 22.176 17.129 23.112 ;
     RECT  16.301 24.384 17.129 25.032 ;
     RECT  16.733 3.072 17.161 6.6 ;
     RECT  17.129 19.296 17.237 21.144 ;
     RECT  17.129 7.92 17.273 18.12 ;
     RECT  17.237 20.448 17.309 21.144 ;
     RECT  17.075 26.112 17.417 27.24 ;
     RECT  17.273 13.104 17.489 18.12 ;
     RECT  17.489 13.104 17.525 16.44 ;
     RECT  17.417 26.112 17.561 26.952 ;
     RECT  17.273 7.92 17.809 12.072 ;
     RECT  17.161 3.072 17.881 6.696 ;
     RECT  17.129 24.384 17.881 24.792 ;
     RECT  17.881 2.208 18.025 6.696 ;
     RECT  17.809 7.68 18.025 12.072 ;
     RECT  17.129 22.176 18.133 22.584 ;
     RECT  17.237 19.296 18.205 19.32 ;
     RECT  17.309 20.448 18.205 20.472 ;
     RECT  18.133 21.504 18.277 22.584 ;
     RECT  17.881 23.664 18.277 24.792 ;
     RECT  17.561 26.112 18.277 26.136 ;
     RECT  18.205 19.296 18.313 20.472 ;
     RECT  18.277 21.504 18.313 24.792 ;
     RECT  18.277 26.064 18.313 26.136 ;
     RECT  17.489 18.096 18.457 18.12 ;
     RECT  18.025 2.208 18.565 12.072 ;
     RECT  18.565 2.208 18.608 12.264 ;
     RECT  17.525 13.536 18.608 16.44 ;
     RECT  18.457 17.616 18.608 18.12 ;
     RECT  18.313 19.296 18.608 26.136 ;
     RECT  18.608 2.148 18.712 28.092 ;
     RECT  18.712 2.148 18.904 27.822 ;
     RECT  18.904 15.792 18.965 26.904 ;
     RECT  18.904 2.148 19.073 14.664 ;
     RECT  19.073 2.148 19.109 14.184 ;
     RECT  19.109 10.224 19.217 14.184 ;
     RECT  19.109 2.148 19.357 9.048 ;
     RECT  18.965 15.984 19.757 26.904 ;
     RECT  19.757 16.272 20.045 26.904 ;
     RECT  20.045 26.784 20.185 26.904 ;
     RECT  20.045 16.272 20.261 25.272 ;
     RECT  19.357 1.968 20.329 9.048 ;
     RECT  19.217 10.224 20.365 14.088 ;
     RECT  20.261 20.352 20.621 25.272 ;
     RECT  20.329 1.584 20.657 9.048 ;
     RECT  20.261 16.272 20.657 19.272 ;
     RECT  20.657 1.584 20.693 5.016 ;
     RECT  20.185 26.784 20.693 26.952 ;
     RECT  20.621 20.592 20.945 25.272 ;
     RECT  20.365 10.224 21.017 14.472 ;
     RECT  20.657 6.048 21.085 9.048 ;
     RECT  20.945 21.168 21.085 25.272 ;
     RECT  20.693 1.584 21.121 4.776 ;
     RECT  21.085 6.048 21.445 9.192 ;
     RECT  21.017 10.224 21.445 10.728 ;
     RECT  20.657 16.272 21.445 18.504 ;
     RECT  20.693 26.928 21.445 26.952 ;
     RECT  21.085 21.168 21.481 25.32 ;
     RECT  21.445 26.928 21.481 27.24 ;
     RECT  21.121 1.296 21.661 4.776 ;
     RECT  21.445 6.048 21.661 10.728 ;
     RECT  21.017 11.76 21.661 14.472 ;
     RECT  21.445 15.504 21.661 18.504 ;
     RECT  21.481 26.928 21.661 27.336 ;
     RECT  21.661 26.928 21.697 27.528 ;
     RECT  21.481 21.168 21.805 25.896 ;
     RECT  21.697 26.928 21.805 27.624 ;
     RECT  21.661 1.296 22.201 10.728 ;
     RECT  21.661 11.76 22.201 18.504 ;
     RECT  22.201 1.2 22.237 18.504 ;
     RECT  21.805 20.016 22.237 20.04 ;
     RECT  21.805 21.168 22.237 27.624 ;
     RECT  22.237 0.816 22.381 18.504 ;
     RECT  22.381 0.816 22.741 18.792 ;
     RECT  22.237 19.92 22.741 27.624 ;
     RECT  22.741 0.816 22.849 27.816 ;
     RECT  22.849 0.816 23.641 27.912 ;
     RECT  23.641 0.72 23.724 27.912 ;
    LAYER M5 ;
     RECT  2.4 2.137 2.52 2.151 ;
     RECT  7.8 2.137 7.92 2.151 ;
     RECT  13.2 2.137 13.32 2.151 ;
     RECT  18.6 2.137 18.72 2.151 ;
     RECT  13.2 2.151 13.512 2.581 ;
     RECT  7.8 2.151 8.112 3.397 ;
     RECT  13.2 2.581 14.328 3.443 ;
     RECT  0.144 3.733 0.168 3.923 ;
     RECT  5.616 3.397 5.64 4.115 ;
     RECT  7.68 3.397 8.112 5.123 ;
     RECT  2.4 2.151 2.712 5.221 ;
     RECT  13.2 3.443 13.896 5.989 ;
     RECT  12.912 5.989 13.896 6.131 ;
     RECT  2.4 5.221 3.096 6.181 ;
     RECT  13.2 6.131 13.896 6.277 ;
     RECT  13.2 6.277 14.856 6.805 ;
     RECT  13.2 6.805 15.192 6.851 ;
     RECT  0.144 5.989 0.168 6.947 ;
     RECT  2.304 6.181 3.096 7.333 ;
     RECT  2.304 7.333 3.144 7.523 ;
     RECT  4.368 6.181 4.392 7.765 ;
     RECT  2.304 7.523 3.096 7.811 ;
     RECT  4.368 7.765 4.632 7.811 ;
     RECT  13.2 6.851 13.896 7.909 ;
     RECT  15.168 6.851 15.192 7.909 ;
     RECT  13.2 7.909 15.192 8.003 ;
     RECT  12 6.133 12.024 8.483 ;
     RECT  9.888 5.461 9.912 8.629 ;
     RECT  9.696 8.629 9.912 8.675 ;
     RECT  13.2 8.003 14.424 9.011 ;
     RECT  4.608 7.811 4.632 9.155 ;
     RECT  2.4 7.811 3.096 10.165 ;
     RECT  4.8 9.685 4.824 10.595 ;
     RECT  2.304 10.165 3.096 10.789 ;
     RECT  9.696 8.675 9.72 10.837 ;
     RECT  9.696 10.837 10.152 11.653 ;
     RECT  13.2 9.011 13.944 12.083 ;
     RECT  2.304 10.789 3.96 12.515 ;
     RECT  2.4 12.515 3.96 12.517 ;
     RECT  0.336 11.845 0.36 12.805 ;
     RECT  13.2 12.083 13.896 12.805 ;
     RECT  0.288 12.805 0.36 13.573 ;
     RECT  0.24 13.573 0.36 13.619 ;
     RECT  0.24 13.619 0.264 13.763 ;
     RECT  12.528 12.805 13.896 13.955 ;
     RECT  9.648 11.653 10.152 14.387 ;
     RECT  15.408 9.541 15.432 14.485 ;
     RECT  14.88 14.485 15.432 14.627 ;
     RECT  6.288 12.757 6.312 14.819 ;
     RECT  2.4 12.517 4.536 15.059 ;
     RECT  2.4 15.059 3.576 15.541 ;
     RECT  9.936 14.387 10.152 15.589 ;
     RECT  15.408 14.627 15.432 15.829 ;
     RECT  9.936 15.589 10.248 16.019 ;
     RECT  0.144 14.101 0.168 16.165 ;
     RECT  7.8 5.123 8.112 16.357 ;
     RECT  13.2 13.955 13.896 16.405 ;
     RECT  0.144 16.165 0.216 16.453 ;
     RECT  2.304 15.541 3.576 16.501 ;
     RECT  14.928 15.829 15.432 16.547 ;
     RECT  6.864 16.357 8.112 16.595 ;
     RECT  0.144 16.453 0.264 16.981 ;
     RECT  2.304 16.501 4.056 17.027 ;
     RECT  12.24 16.405 13.896 17.077 ;
     RECT  0.144 16.981 1.176 17.123 ;
     RECT  5.088 16.981 5.112 17.123 ;
     RECT  0.144 17.123 0.264 17.219 ;
     RECT  11.616 17.077 13.896 17.219 ;
     RECT  2.304 17.027 3.576 17.459 ;
     RECT  11.76 17.219 13.896 17.939 ;
     RECT  15.408 16.547 15.432 17.989 ;
     RECT  16.944 15.493 16.968 17.989 ;
     RECT  7.008 16.595 8.112 18.131 ;
     RECT  15.408 17.989 16.968 18.275 ;
     RECT  6.288 18.133 6.312 18.563 ;
     RECT  10.224 16.019 10.248 18.565 ;
     RECT  2.4 17.459 3.576 18.661 ;
     RECT  12.24 17.939 13.896 18.851 ;
     RECT  0.144 17.219 0.168 19.187 ;
     RECT  9.648 18.565 10.248 19.427 ;
     RECT  2.4 18.661 4.248 19.763 ;
     RECT  16.128 18.275 16.968 19.763 ;
     RECT  7.8 18.131 8.112 19.813 ;
     RECT  6.192 18.757 6.216 20.003 ;
     RECT  7.248 19.813 8.112 20.147 ;
     RECT  10.224 19.427 10.248 20.579 ;
     RECT  12.24 18.851 13.512 20.773 ;
     RECT  16.224 19.763 16.968 21.395 ;
     RECT  7.8 20.147 8.112 21.925 ;
     RECT  9.84 20.821 9.864 21.971 ;
     RECT  2.4 19.763 3.624 22.069 ;
     RECT  7.8 21.925 8.568 22.259 ;
     RECT  14.976 21.349 15 22.259 ;
     RECT  2.4 22.069 3.912 22.261 ;
     RECT  11.904 20.773 13.512 22.789 ;
     RECT  6.528 22.165 6.552 22.883 ;
     RECT  0.288 23.269 0.312 23.365 ;
     RECT  0.144 23.365 0.312 23.411 ;
     RECT  5.136 21.637 5.16 23.411 ;
     RECT  11.424 22.789 13.512 23.411 ;
     RECT  0.144 23.411 0.168 23.651 ;
     RECT  7.8 22.259 8.232 23.893 ;
     RECT  7.8 23.893 9.144 23.987 ;
     RECT  12.24 23.411 13.512 24.563 ;
     RECT  10.32 23.317 10.344 24.661 ;
     RECT  10.32 24.661 10.824 24.707 ;
     RECT  2.4 22.261 3.96 25.139 ;
     RECT  10.8 24.707 10.824 25.139 ;
     RECT  12.192 25.045 12.216 25.475 ;
     RECT  13.2 24.563 13.512 25.717 ;
     RECT  6.336 23.317 6.36 26.005 ;
     RECT  3.936 25.139 3.96 26.099 ;
     RECT  5.664 26.005 6.36 26.147 ;
     RECT  9.12 23.987 9.144 26.579 ;
     RECT  13.2 25.717 13.608 26.579 ;
     RECT  16.944 21.395 16.968 27.301 ;
     RECT  5.664 26.147 5.688 27.347 ;
     RECT  0.144 26.869 0.168 27.829 ;
     RECT  2.4 25.139 2.712 28.089 ;
     RECT  7.8 23.987 8.112 28.089 ;
     RECT  13.2 26.579 13.512 28.089 ;
     RECT  18.6 2.151 18.912 28.089 ;
     RECT  2.4 28.089 2.52 28.103 ;
     RECT  7.8 28.089 7.92 28.103 ;
     RECT  13.2 28.089 13.32 28.103 ;
     RECT  18.6 28.089 18.72 28.103 ;
     RECT  0.144 27.829 0.552 28.595 ;
     RECT  0.528 28.595 0.552 29.267 ;
     RECT  16.944 27.301 17.064 30.224 ;
     RECT  12.912 6.131 13.2 6.133 ;
     RECT  12.024 6.133 13.2 8.483 ;
     RECT  3.096 6.181 4.368 7.333 ;
     RECT  13.896 6.851 15.168 7.909 ;
     RECT  3.144 7.333 4.368 7.523 ;
     RECT  3.096 7.523 4.368 7.811 ;
     RECT  3.096 7.811 4.608 9.155 ;
     RECT  13.944 9.011 14.424 9.541 ;
     RECT  13.944 9.541 15.408 12.083 ;
     RECT  13.896 12.083 15.408 14.485 ;
     RECT  6.312 12.757 7.8 14.819 ;
     RECT  13.896 14.485 14.88 14.627 ;
     RECT  13.896 14.627 15.408 15.829 ;
     RECT  3.576 15.059 4.056 16.501 ;
     RECT  15.432 15.493 16.944 17.989 ;
     RECT  13.896 15.829 14.928 16.547 ;
     RECT  13.896 16.547 15.408 18.275 ;
     RECT  1.176 16.981 2.304 17.123 ;
     RECT  4.056 16.981 5.088 17.027 ;
     RECT  3.576 17.027 5.088 17.123 ;
     RECT  10.248 17.077 11.616 17.219 ;
     RECT  10.248 17.219 11.76 17.939 ;
     RECT  7.008 18.131 7.8 18.133 ;
     RECT  6.312 18.133 7.8 18.563 ;
     RECT  6.288 18.563 7.8 18.757 ;
     RECT  6.216 18.757 7.8 19.813 ;
     RECT  9.84 19.427 10.224 20.579 ;
     RECT  6.216 19.813 7.248 20.003 ;
     RECT  9.84 20.579 9.864 20.821 ;
     RECT  13.512 21.349 14.976 22.259 ;
     RECT  15 21.349 16.224 21.395 ;
     RECT  3.624 21.637 5.136 22.069 ;
     RECT  8.568 21.925 9.84 21.971 ;
     RECT  3.912 22.069 5.136 22.261 ;
     RECT  5.16 22.165 6.528 22.883 ;
     RECT  6.552 22.165 7.8 22.883 ;
     RECT  3.96 22.261 5.136 23.411 ;
     RECT  5.16 22.883 7.8 23.317 ;
     RECT  5.16 23.317 6.336 23.411 ;
     RECT  6.36 23.317 7.8 26.147 ;
     RECT  10.344 23.317 11.424 23.411 ;
     RECT  10.344 23.411 12.24 24.563 ;
     RECT  9.144 23.893 10.32 24.707 ;
     RECT  8.112 23.987 9.12 26.579 ;
     RECT  10.344 24.563 13.2 24.661 ;
     RECT  10.824 24.661 13.2 25.045 ;
     RECT  10.824 25.045 12.192 25.139 ;
     RECT  12.216 25.045 13.2 25.475 ;
     RECT  2.712 25.139 3.936 26.099 ;
  END
END dsfd_rly_276_WE
END LIBRARY
